VERSION 5.8 ;
BUSBITCHARS "[]" ;
DIVIDERCHAR "/" ;

PROPERTYDEFINITIONS
  MACRO pathCL STRING ;
  MACRO arrayDisplay STRING ;
  MACRO instLabel STRING ;
  MACRO startLevel INTEGER ;
  MACRO stopLevel INTEGER ;
  MACRO scrollPercent INTEGER ;
  MACRO gridSpacing REAL ;
  MACRO gridMultiple INTEGER ;
  MACRO xSnapSpacing REAL ;
  MACRO ySnapSpacing REAL ;
  MACRO snapMode STRING ;
  MACRO segSnapMode STRING ;
  MACRO instanceDrawingMode STRING ;
  MACRO lppVisibilityMode STRING ;
  MACRO filterSize REAL ;
  MACRO filterSizeDrawingStyle STRING ;
  MACRO displayResolution STRING ;
  MACRO dimmingScope STRING ;
  MACRO dimmingIntensity INTEGER ;
  MACRO autoZoomMode STRING ;
  MACRO autoZoomScale INTEGER ;
  MACRO mergeScope STRING ;
  LAYER LEF58_TYPE STRING ;
END PROPERTYDEFINITIONS


LAYER well
  TYPE MASTERSLICE ;
  PROPERTY LEF58_TYPE "TYPE NWELL ;" ;
END well

LAYER Gate
  TYPE MASTERSLICE ;
END Gate

LAYER Active
  TYPE MASTERSLICE ;
  PROPERTY LEF58_TYPE "TYPE DIFFUSION ;" ;
END Active

LAYER LISD
  TYPE MASTERSLICE ;
  PROPERTY LEF58_TYPE "TYPE MEOL ;" ;
END LISD

LAYER LIG
  TYPE MASTERSLICE ;
  PROPERTY LEF58_TYPE "TYPE MEOL ;" ;
END LIG


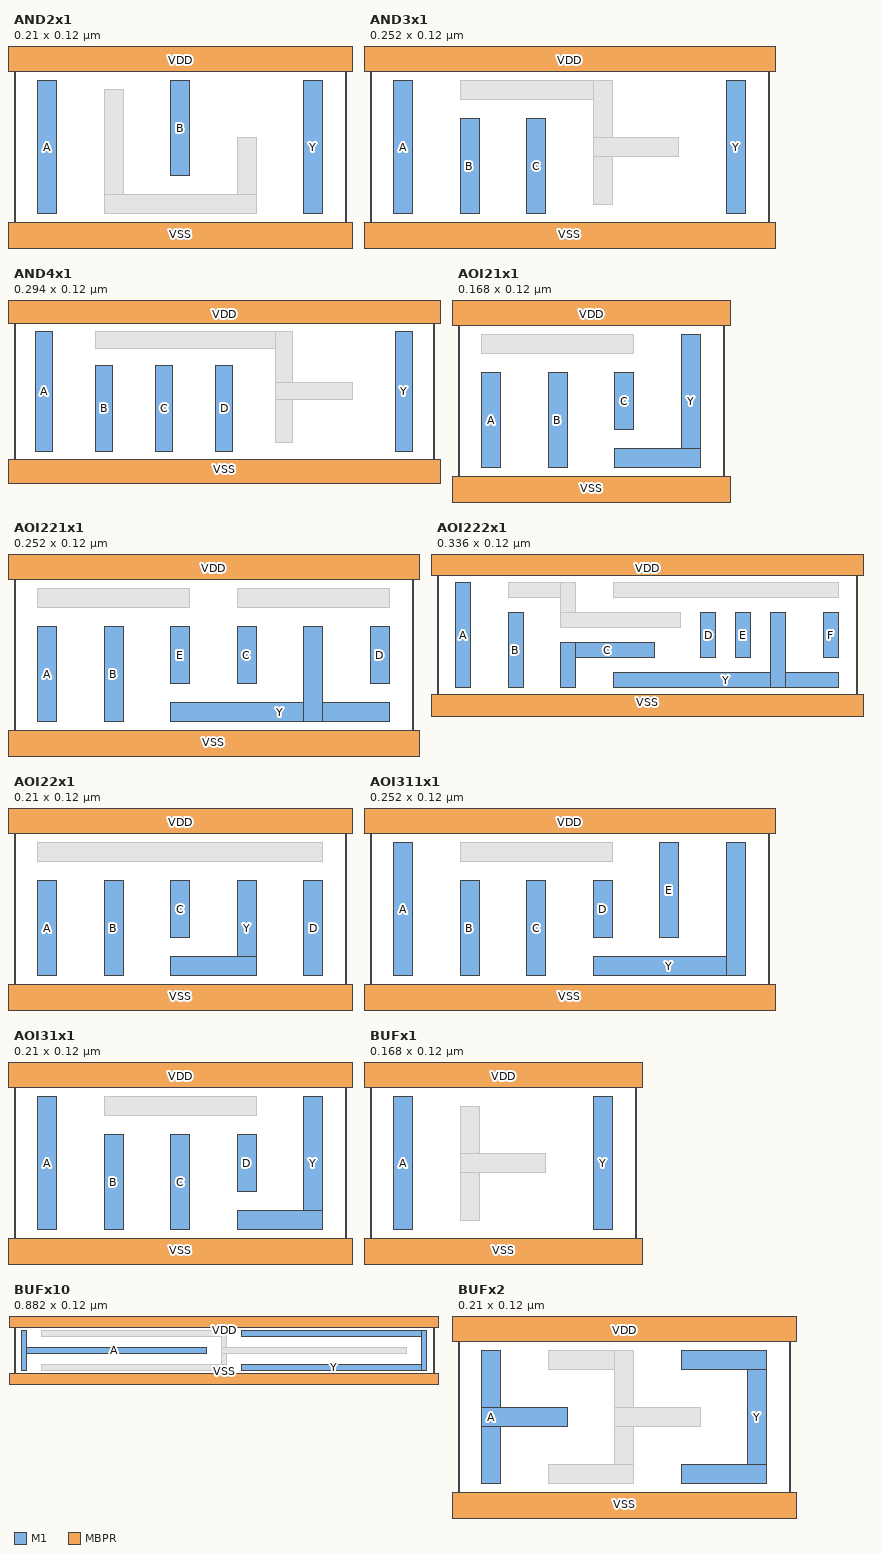
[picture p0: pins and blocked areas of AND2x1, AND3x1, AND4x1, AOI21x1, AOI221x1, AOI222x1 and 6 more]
MACRO AND2x1
  CLASS CORE ;
  ORIGIN 0 0 ;
  FOREIGN AND2x1 0 0 ;
  SIZE 0.21 BY 0.12 ;
  SYMMETRY X Y ;
  SITE coreSite ;
  PIN A
    DIRECTION INPUT ;
    USE SIGNAL ;
    PORT
      LAYER M1 ;
        RECT 0.015 0.018 0.027 0.102 ;
    END
  END A
  PIN B
    DIRECTION INPUT ;
    USE SIGNAL ;
    PORT
      LAYER M1 ;
        RECT 0.099 0.042 0.111 0.102 ;
    END
  END B
  PIN VDD
    DIRECTION INOUT ;
    USE POWER ;
    SHAPE ABUTMENT ;
    PORT
      LAYER MBPR ;
        RECT -0.009 0.1075 0.219 0.1325 ;
    END
  END VDD
  PIN VSS
    DIRECTION INOUT ;
    USE GROUND ;
    SHAPE ABUTMENT ;
    PORT
      LAYER MBPR ;
        RECT -0.009 -0.0125 0.219 0.0125 ;
    END
  END VSS
  PIN Y
    DIRECTION OUTPUT ;
    USE SIGNAL ;
    PORT
      LAYER M1 ;
        RECT 0.183 0.018 0.195 0.102 ;
    END
  END Y
  OBS
    LAYER M1 ;
      RECT 0.057 0.018 0.069 0.096 ;
      RECT 0.141 0.018 0.153 0.066 ;
      RECT 0.057 0.018 0.153 0.03 ;
    LAYER VBPR ;
      RECT 0.011 -0.006 0.031 0.006 ;
      RECT 0.137 -0.006 0.157 0.006 ;
      RECT 0.011 0.114 0.031 0.126 ;
      RECT 0.137 0.114 0.157 0.126 ;
      RECT 0.095 0.114 0.115 0.126 ;
  END
END AND2x1

MACRO AND3x1
  CLASS CORE ;
  ORIGIN 0 0 ;
  FOREIGN AND3x1 0 0 ;
  SIZE 0.252 BY 0.12 ;
  SYMMETRY X Y ;
  SITE coreSite ;
  PIN A
    DIRECTION INPUT ;
    USE SIGNAL ;
    PORT
      LAYER M1 ;
        RECT 0.015 0.018 0.027 0.102 ;
    END
  END A
  PIN B
    DIRECTION INPUT ;
    USE SIGNAL ;
    PORT
      LAYER M1 ;
        RECT 0.057 0.018 0.069 0.078 ;
    END
  END B
  PIN C
    DIRECTION INPUT ;
    USE SIGNAL ;
    PORT
      LAYER M1 ;
        RECT 0.099 0.018 0.111 0.078 ;
    END
  END C
  PIN VDD
    DIRECTION INOUT ;
    USE POWER ;
    SHAPE ABUTMENT ;
    PORT
      LAYER MBPR ;
        RECT -0.009 0.1075 0.261 0.1325 ;
    END
  END VDD
  PIN VSS
    DIRECTION INOUT ;
    USE GROUND ;
    SHAPE ABUTMENT ;
    PORT
      LAYER MBPR ;
        RECT -0.009 -0.0125 0.261 0.0125 ;
    END
  END VSS
  PIN Y
    DIRECTION OUTPUT ;
    USE SIGNAL ;
    PORT
      LAYER M1 ;
        RECT 0.225 0.018 0.237 0.102 ;
    END
  END Y
  OBS
    LAYER M1 ;
      RECT 0.057 0.09 0.153 0.102 ;
      RECT 0.141 0.024 0.153 0.102 ;
      RECT 0.141 0.054 0.195 0.066 ;
    LAYER VBPR ;
      RECT 0.011 -0.006 0.031 0.006 ;
      RECT 0.179 -0.006 0.199 0.006 ;
      RECT 0.011 0.114 0.031 0.126 ;
      RECT 0.179 0.114 0.199 0.126 ;
      RECT 0.095 0.114 0.115 0.126 ;
  END
END AND3x1

MACRO AND4x1
  CLASS CORE ;
  ORIGIN 0 0 ;
  FOREIGN AND4x1 0 0 ;
  SIZE 0.294 BY 0.12 ;
  SYMMETRY X Y ;
  SITE coreSite ;
  PIN A
    DIRECTION INPUT ;
    USE SIGNAL ;
    PORT
      LAYER M1 ;
        RECT 0.015 0.018 0.027 0.102 ;
    END
  END A
  PIN B
    DIRECTION INPUT ;
    USE SIGNAL ;
    PORT
      LAYER M1 ;
        RECT 0.057 0.018 0.069 0.078 ;
    END
  END B
  PIN C
    DIRECTION INPUT ;
    USE SIGNAL ;
    PORT
      LAYER M1 ;
        RECT 0.099 0.018 0.111 0.078 ;
    END
  END C
  PIN D
    DIRECTION INPUT ;
    USE SIGNAL ;
    PORT
      LAYER M1 ;
        RECT 0.141 0.018 0.153 0.078 ;
    END
  END D
  PIN VDD
    DIRECTION INOUT ;
    USE POWER ;
    SHAPE ABUTMENT ;
    PORT
      LAYER MBPR ;
        RECT -0.009 0.1075 0.303 0.1325 ;
    END
  END VDD
  PIN VSS
    DIRECTION INOUT ;
    USE GROUND ;
    SHAPE ABUTMENT ;
    PORT
      LAYER MBPR ;
        RECT -0.009 -0.0125 0.303 0.0125 ;
    END
  END VSS
  PIN Y
    DIRECTION OUTPUT ;
    USE SIGNAL ;
    PORT
      LAYER M1 ;
        RECT 0.267 0.018 0.279 0.102 ;
    END
  END Y
  OBS
    LAYER M1 ;
      RECT 0.057 0.09 0.195 0.102 ;
      RECT 0.183 0.024 0.195 0.102 ;
      RECT 0.183 0.054 0.237 0.066 ;
    LAYER VBPR ;
      RECT 0.011 -0.006 0.031 0.006 ;
      RECT 0.221 -0.006 0.241 0.006 ;
      RECT 0.011 0.114 0.031 0.126 ;
      RECT 0.221 0.114 0.241 0.126 ;
      RECT 0.095 0.114 0.115 0.126 ;
      RECT 0.179 0.114 0.199 0.126 ;
  END
END AND4x1

MACRO AOI21x1
  CLASS CORE ;
  ORIGIN 0 0 ;
  FOREIGN AOI21x1 0 0 ;
  SIZE 0.168 BY 0.12 ;
  SYMMETRY X Y ;
  SITE coreSite ;
  PIN A
    DIRECTION INPUT ;
    USE SIGNAL ;
    PORT
      LAYER M1 ;
        RECT 0.015 0.018 0.027 0.078 ;
    END
  END A
  PIN B
    DIRECTION INPUT ;
    USE SIGNAL ;
    PORT
      LAYER M1 ;
        RECT 0.057 0.018 0.069 0.078 ;
    END
  END B
  PIN C
    DIRECTION INPUT ;
    USE SIGNAL ;
    PORT
      LAYER M1 ;
        RECT 0.099 0.042 0.111 0.078 ;
    END
  END C
  PIN VDD
    DIRECTION INOUT ;
    USE POWER ;
    SHAPE ABUTMENT ;
    PORT
      LAYER MBPR ;
        RECT -0.009 0.1075 0.177 0.1325 ;
    END
  END VDD
  PIN VSS
    DIRECTION INOUT ;
    USE GROUND ;
    SHAPE ABUTMENT ;
    PORT
      LAYER MBPR ;
        RECT -0.009 -0.0125 0.177 0.0125 ;
    END
  END VSS
  PIN Y
    DIRECTION OUTPUT ;
    USE SIGNAL ;
    PORT
      LAYER M1 ;
        RECT 0.141 0.018 0.153 0.102 ;
        RECT 0.099 0.018 0.153 0.03 ;
    END
  END Y
  OBS
    LAYER M1 ;
      RECT 0.015 0.09 0.111 0.102 ;
    LAYER VBPR ;
      RECT 0.011 -0.006 0.031 0.006 ;
      RECT 0.137 -0.006 0.157 0.006 ;
      RECT 0.053 0.114 0.073 0.126 ;
  END
END AOI21x1

MACRO AOI221x1
  CLASS CORE ;
  ORIGIN 0 0 ;
  FOREIGN AOI221x1 0 0 ;
  SIZE 0.252 BY 0.12 ;
  SYMMETRY X Y ;
  SITE coreSite ;
  PIN A
    DIRECTION INPUT ;
    USE SIGNAL ;
    PORT
      LAYER M1 ;
        RECT 0.015 0.018 0.027 0.078 ;
    END
  END A
  PIN B
    DIRECTION INPUT ;
    USE SIGNAL ;
    PORT
      LAYER M1 ;
        RECT 0.057 0.018 0.069 0.078 ;
    END
  END B
  PIN C
    DIRECTION INPUT ;
    USE SIGNAL ;
    PORT
      LAYER M1 ;
        RECT 0.141 0.042 0.153 0.078 ;
    END
  END C
  PIN D
    DIRECTION INPUT ;
    USE SIGNAL ;
    PORT
      LAYER M1 ;
        RECT 0.225 0.042 0.237 0.078 ;
    END
  END D
  PIN E
    DIRECTION INPUT ;
    USE SIGNAL ;
    PORT
      LAYER M1 ;
        RECT 0.099 0.042 0.111 0.078 ;
    END
  END E
  PIN VDD
    DIRECTION INOUT ;
    USE POWER ;
    SHAPE ABUTMENT ;
    PORT
      LAYER MBPR ;
        RECT -0.009 0.1075 0.261 0.1325 ;
    END
  END VDD
  PIN VSS
    DIRECTION INOUT ;
    USE GROUND ;
    SHAPE ABUTMENT ;
    PORT
      LAYER MBPR ;
        RECT -0.009 -0.0125 0.261 0.0125 ;
    END
  END VSS
  PIN Y
    DIRECTION OUTPUT ;
    USE SIGNAL ;
    PORT
      LAYER M1 ;
        RECT 0.099 0.018 0.237 0.03 ;
        RECT 0.183 0.018 0.195 0.078 ;
    END
  END Y
  OBS
    LAYER M1 ;
      RECT 0.141 0.09 0.237 0.102 ;
      RECT 0.015 0.09 0.111 0.102 ;
    LAYER VBPR ;
      RECT 0.011 -0.006 0.031 0.006 ;
      RECT 0.137 -0.006 0.157 0.006 ;
      RECT 0.053 0.114 0.073 0.126 ;
  END
END AOI221x1

MACRO AOI222x1
  CLASS CORE ;
  ORIGIN 0 0 ;
  FOREIGN AOI222x1 0 0 ;
  SIZE 0.336 BY 0.12 ;
  SYMMETRY X Y ;
  SITE coreSite ;
  PIN A
    DIRECTION INPUT ;
    USE SIGNAL ;
    PORT
      LAYER M1 ;
        RECT 0.015 0.018 0.027 0.102 ;
    END
  END A
  PIN B
    DIRECTION INPUT ;
    USE SIGNAL ;
    PORT
      LAYER M1 ;
        RECT 0.057 0.018 0.069 0.078 ;
    END
  END B
  PIN C
    DIRECTION INPUT ;
    USE SIGNAL ;
    PORT
      LAYER M1 ;
        RECT 0.099 0.042 0.174 0.054 ;
        RECT 0.099 0.018 0.111 0.054 ;
    END
  END C
  PIN D
    DIRECTION INPUT ;
    USE SIGNAL ;
    PORT
      LAYER M1 ;
        RECT 0.211 0.042 0.223 0.078 ;
    END
  END D
  PIN E
    DIRECTION INPUT ;
    USE SIGNAL ;
    PORT
      LAYER M1 ;
        RECT 0.239 0.042 0.251 0.078 ;
    END
  END E
  PIN F
    DIRECTION INPUT ;
    USE SIGNAL ;
    PORT
      LAYER M1 ;
        RECT 0.309 0.042 0.321 0.078 ;
    END
  END F
  PIN VDD
    DIRECTION INOUT ;
    USE POWER ;
    SHAPE ABUTMENT ;
    PORT
      LAYER MBPR ;
        RECT -0.009 0.1075 0.345 0.1325 ;
    END
  END VDD
  PIN VSS
    DIRECTION INOUT ;
    USE GROUND ;
    SHAPE ABUTMENT ;
    PORT
      LAYER MBPR ;
        RECT -0.009 -0.0125 0.345 0.0125 ;
    END
  END VSS
  PIN Y
    DIRECTION OUTPUT ;
    USE SIGNAL ;
    PORT
      LAYER M1 ;
        RECT 0.141 0.018 0.321 0.03 ;
        RECT 0.267 0.018 0.279 0.078 ;
    END
  END Y
  OBS
    LAYER M1 ;
      RECT 0.057 0.09 0.111 0.102 ;
      RECT 0.099 0.066 0.111 0.102 ;
      RECT 0.099 0.066 0.195 0.078 ;
      RECT 0.141 0.09 0.321 0.102 ;
    LAYER VBPR ;
      RECT 0.011 -0.006 0.031 0.006 ;
      RECT 0.221 -0.006 0.241 0.006 ;
      RECT 0.011 0.114 0.031 0.126 ;
      RECT 0.095 0.114 0.115 0.126 ;
  END
END AOI222x1

MACRO AOI22x1
  CLASS CORE ;
  ORIGIN 0 0 ;
  FOREIGN AOI22x1 0 0 ;
  SIZE 0.21 BY 0.12 ;
  SYMMETRY X Y ;
  SITE coreSite ;
  PIN A
    DIRECTION INPUT ;
    USE SIGNAL ;
    PORT
      LAYER M1 ;
        RECT 0.015 0.018 0.027 0.078 ;
    END
  END A
  PIN B
    DIRECTION INPUT ;
    USE SIGNAL ;
    PORT
      LAYER M1 ;
        RECT 0.057 0.018 0.069 0.078 ;
    END
  END B
  PIN C
    DIRECTION INPUT ;
    USE SIGNAL ;
    PORT
      LAYER M1 ;
        RECT 0.099 0.042 0.111 0.078 ;
    END
  END C
  PIN D
    DIRECTION INPUT ;
    USE SIGNAL ;
    PORT
      LAYER M1 ;
        RECT 0.183 0.018 0.195 0.078 ;
    END
  END D
  PIN VDD
    DIRECTION INOUT ;
    USE POWER ;
    SHAPE ABUTMENT ;
    PORT
      LAYER MBPR ;
        RECT -0.009 0.1075 0.219 0.1325 ;
    END
  END VDD
  PIN VSS
    DIRECTION INOUT ;
    USE GROUND ;
    SHAPE ABUTMENT ;
    PORT
      LAYER MBPR ;
        RECT -0.009 -0.0125 0.219 0.0125 ;
    END
  END VSS
  PIN Y
    DIRECTION OUTPUT ;
    USE SIGNAL ;
    PORT
      LAYER M1 ;
        RECT 0.141 0.018 0.153 0.078 ;
        RECT 0.099 0.018 0.153 0.03 ;
    END
  END Y
  OBS
    LAYER M1 ;
      RECT 0.015 0.09 0.195 0.102 ;
    LAYER VBPR ;
      RECT 0.011 -0.006 0.031 0.006 ;
      RECT 0.179 -0.006 0.199 0.006 ;
      RECT 0.053 0.114 0.073 0.126 ;
  END
END AOI22x1

MACRO AOI311x1
  CLASS CORE ;
  ORIGIN 0 0 ;
  FOREIGN AOI311x1 0 0 ;
  SIZE 0.252 BY 0.12 ;
  SYMMETRY X Y ;
  SITE coreSite ;
  PIN A
    DIRECTION INPUT ;
    USE SIGNAL ;
    PORT
      LAYER M1 ;
        RECT 0.015 0.018 0.027 0.102 ;
    END
  END A
  PIN B
    DIRECTION INPUT ;
    USE SIGNAL ;
    PORT
      LAYER M1 ;
        RECT 0.057 0.018 0.069 0.078 ;
    END
  END B
  PIN C
    DIRECTION INPUT ;
    USE SIGNAL ;
    PORT
      LAYER M1 ;
        RECT 0.099 0.018 0.111 0.078 ;
    END
  END C
  PIN D
    DIRECTION INPUT ;
    USE SIGNAL ;
    PORT
      LAYER M1 ;
        RECT 0.141 0.042 0.153 0.078 ;
    END
  END D
  PIN E
    DIRECTION INPUT ;
    USE SIGNAL ;
    PORT
      LAYER M1 ;
        RECT 0.183 0.042 0.195 0.102 ;
    END
  END E
  PIN VDD
    DIRECTION INOUT ;
    USE POWER ;
    SHAPE ABUTMENT ;
    PORT
      LAYER MBPR ;
        RECT -0.009 0.1075 0.261 0.1325 ;
    END
  END VDD
  PIN VSS
    DIRECTION INOUT ;
    USE GROUND ;
    SHAPE ABUTMENT ;
    PORT
      LAYER MBPR ;
        RECT -0.009 -0.0125 0.261 0.0125 ;
    END
  END VSS
  PIN Y
    DIRECTION OUTPUT ;
    USE SIGNAL ;
    PORT
      LAYER M1 ;
        RECT 0.225 0.018 0.237 0.102 ;
        RECT 0.141 0.018 0.237 0.03 ;
    END
  END Y
  OBS
    LAYER M1 ;
      RECT 0.057 0.09 0.153 0.102 ;
    LAYER VBPR ;
      RECT 0.011 -0.006 0.031 0.006 ;
      RECT 0.179 -0.006 0.199 0.006 ;
      RECT 0.011 0.114 0.031 0.126 ;
      RECT 0.095 0.114 0.115 0.126 ;
  END
END AOI311x1

MACRO AOI31x1
  CLASS CORE ;
  ORIGIN 0 0 ;
  FOREIGN AOI31x1 0 0 ;
  SIZE 0.21 BY 0.12 ;
  SYMMETRY X Y ;
  SITE coreSite ;
  PIN A
    DIRECTION INPUT ;
    USE SIGNAL ;
    PORT
      LAYER M1 ;
        RECT 0.015 0.018 0.027 0.102 ;
    END
  END A
  PIN B
    DIRECTION INPUT ;
    USE SIGNAL ;
    PORT
      LAYER M1 ;
        RECT 0.057 0.018 0.069 0.078 ;
    END
  END B
  PIN C
    DIRECTION INPUT ;
    USE SIGNAL ;
    PORT
      LAYER M1 ;
        RECT 0.099 0.018 0.111 0.078 ;
    END
  END C
  PIN D
    DIRECTION INPUT ;
    USE SIGNAL ;
    PORT
      LAYER M1 ;
        RECT 0.141 0.042 0.153 0.078 ;
    END
  END D
  PIN VDD
    DIRECTION INOUT ;
    USE POWER ;
    SHAPE ABUTMENT ;
    PORT
      LAYER MBPR ;
        RECT -0.009 0.1075 0.219 0.1325 ;
    END
  END VDD
  PIN VSS
    DIRECTION INOUT ;
    USE GROUND ;
    SHAPE ABUTMENT ;
    PORT
      LAYER MBPR ;
        RECT -0.009 -0.0125 0.219 0.0125 ;
    END
  END VSS
  PIN Y
    DIRECTION OUTPUT ;
    USE SIGNAL ;
    PORT
      LAYER M1 ;
        RECT 0.183 0.018 0.195 0.102 ;
        RECT 0.141 0.018 0.195 0.03 ;
    END
  END Y
  OBS
    LAYER M1 ;
      RECT 0.057 0.09 0.153 0.102 ;
    LAYER VBPR ;
      RECT 0.011 -0.006 0.031 0.006 ;
      RECT 0.179 -0.006 0.199 0.006 ;
      RECT 0.011 0.114 0.031 0.126 ;
      RECT 0.095 0.114 0.115 0.126 ;
  END
END AOI31x1

MACRO BUFx1
  CLASS CORE ;
  ORIGIN 0 0 ;
  FOREIGN BUFx1 0 0 ;
  SIZE 0.168 BY 0.12 ;
  SYMMETRY X Y ;
  SITE coreSite ;
  PIN A
    DIRECTION INPUT ;
    USE SIGNAL ;
    PORT
      LAYER M1 ;
        RECT 0.015 0.018 0.027 0.102 ;
    END
  END A
  PIN VDD
    DIRECTION INOUT ;
    USE POWER ;
    SHAPE ABUTMENT ;
    PORT
      LAYER MBPR ;
        RECT -0.009 0.1075 0.177 0.1325 ;
    END
  END VDD
  PIN VSS
    DIRECTION INOUT ;
    USE GROUND ;
    SHAPE ABUTMENT ;
    PORT
      LAYER MBPR ;
        RECT -0.009 -0.0125 0.177 0.0125 ;
    END
  END VSS
  PIN Y
    DIRECTION OUTPUT ;
    USE SIGNAL ;
    PORT
      LAYER M1 ;
        RECT 0.141 0.018 0.153 0.102 ;
    END
  END Y
  OBS
    LAYER M1 ;
      RECT 0.057 0.024 0.069 0.096 ;
      RECT 0.057 0.054 0.111 0.066 ;
    LAYER VBPR ;
      RECT 0.011 -0.006 0.031 0.006 ;
      RECT 0.095 -0.006 0.115 0.006 ;
      RECT 0.011 0.114 0.031 0.126 ;
      RECT 0.095 0.114 0.115 0.126 ;
  END
END BUFx1

MACRO BUFx10
  CLASS CORE ;
  ORIGIN 0 0 ;
  FOREIGN BUFx10 0 0 ;
  SIZE 0.882 BY 0.12 ;
  SYMMETRY X Y ;
  SITE coreSite ;
  PIN A
    DIRECTION INPUT ;
    USE SIGNAL ;
    PORT
      LAYER M1 ;
        RECT 0.015 0.054 0.405 0.066 ;
        RECT 0.015 0.018 0.027 0.102 ;
    END
  END A
  PIN VDD
    DIRECTION INOUT ;
    USE POWER ;
    SHAPE ABUTMENT ;
    PORT
      LAYER MBPR ;
        RECT -0.009 0.1075 0.891 0.1325 ;
    END
  END VDD
  PIN VSS
    DIRECTION INOUT ;
    USE GROUND ;
    SHAPE ABUTMENT ;
    PORT
      LAYER MBPR ;
        RECT -0.009 -0.0125 0.891 0.0125 ;
    END
  END VSS
  PIN Y
    DIRECTION OUTPUT ;
    USE SIGNAL ;
    PORT
      LAYER M1 ;
        RECT 0.477 0.09 0.867 0.102 ;
        RECT 0.855 0.018 0.867 0.102 ;
        RECT 0.477 0.018 0.867 0.03 ;
    END
  END Y
  OBS
    LAYER M1 ;
      RECT 0.057 0.09 0.447 0.102 ;
      RECT 0.435 0.018 0.447 0.102 ;
      RECT 0.435 0.054 0.825 0.066 ;
      RECT 0.057 0.018 0.447 0.03 ;
    LAYER VBPR ;
      RECT 0.011 -0.006 0.031 0.006 ;
      RECT 0.011 0.114 0.031 0.126 ;
      RECT 0.095 -0.006 0.115 0.006 ;
      RECT 0.095 0.114 0.115 0.126 ;
      RECT 0.179 -0.006 0.199  0.006 ;
      RECT 0.179  0.114 0.199  0.126 ;
      RECT 0.263 -0.006 0.283  0.006 ;
      RECT 0.263  0.114 0.283  0.126 ;
      RECT 0.347 -0.006 0.367  0.006 ;
      RECT 0.347  0.114 0.367  0.126 ;
      RECT 0.431 -0.006 0.451  0.006 ;
      RECT 0.431  0.114 0.451  0.126 ;
      RECT 0.515 -0.006 0.535  0.006 ;
      RECT 0.515  0.114 0.535  0.126 ;
      RECT 0.599 -0.006 0.619  0.006 ;
      RECT 0.599  0.114 0.619  0.126 ;
      RECT 0.683 -0.006 0.703  0.006 ;
      RECT 0.683  0.114 0.703  0.126 ;
      RECT 0.767 -0.006 0.787  0.006 ;
      RECT 0.767  0.114 0.787  0.126 ;
      RECT 0.851 -0.006 0.871  0.006 ;
      RECT 0.851  0.114 0.871  0.126 ;
  END
  PROPERTY pathCL "yes" ;
  PROPERTY arrayDisplay "Full" ;
  PROPERTY instLabel "master" ;
  PROPERTY startLevel 0 ;
  PROPERTY stopLevel 0 ;
  PROPERTY scrollPercent 25 ;
  PROPERTY gridSpacing 1 ;
  PROPERTY gridMultiple 5 ;
  PROPERTY xSnapSpacing 0.001 ;
  PROPERTY ySnapSpacing 0.001 ;
  PROPERTY snapMode "orthogonal" ;
  PROPERTY segSnapMode "orthogonal" ;
  PROPERTY instanceDrawingMode "BBox" ;
  PROPERTY lppVisibilityMode "donotCheckValidity" ;
  PROPERTY filterSize 6 ;
  PROPERTY filterSizeDrawingStyle "empty" ;
  PROPERTY displayResolution "Medium" ;
  PROPERTY dimmingScope "none" ;
  PROPERTY dimmingIntensity 50 ;
  PROPERTY autoZoomMode "Pan" ;
  PROPERTY autoZoomScale 90 ;
  PROPERTY mergeScope "pcells" ;
END BUFx10

MACRO BUFx2
  CLASS CORE ;
  ORIGIN 0 0 ;
  FOREIGN BUFx2 0 0 ;
  SIZE 0.21 BY 0.12 ;
  SYMMETRY X Y ;
  SITE coreSite ;
  PIN A
    DIRECTION INPUT ;
    USE SIGNAL ;
    PORT
      LAYER M1 ;
        RECT 0.015 0.054 0.069 0.066 ;
        RECT 0.015 0.018 0.027 0.102 ;
    END
  END A
  PIN VDD
    DIRECTION INOUT ;
    USE POWER ;
    SHAPE ABUTMENT ;
    PORT
      LAYER MBPR ;
        RECT -0.009 0.1075 0.219 0.1325 ;
    END
  END VDD
  PIN VSS
    DIRECTION INOUT ;
    USE GROUND ;
    SHAPE ABUTMENT ;
    PORT
      LAYER MBPR ;
        RECT -0.009 -0.0125 0.219 0.0125 ;
    END
  END VSS
  PIN Y
    DIRECTION OUTPUT ;
    USE SIGNAL ;
    PORT
      LAYER M1 ;
        RECT 0.141 0.09 0.195 0.102 ;
        RECT 0.183 0.018 0.195 0.102 ;
        RECT 0.141 0.018 0.195 0.03 ;
    END
  END Y
  OBS
    LAYER M1 ;
      RECT 0.057 0.09 0.111 0.102 ;
      RECT 0.099 0.018 0.111 0.102 ;
      RECT 0.099 0.054 0.153 0.066 ;
      RECT 0.057 0.018 0.111 0.03 ;
    LAYER VBPR ;
      RECT 0.011 -0.006 0.031 0.006 ;
      RECT 0.011 0.114 0.031 0.126 ;
      RECT 0.095 -0.006 0.115 0.006 ;
      RECT 0.095 0.114 0.115 0.126 ;
      RECT 0.179 -0.006 0.199  0.006 ;
      RECT 0.179  0.114 0.199  0.126 ;
  END
END BUFx2

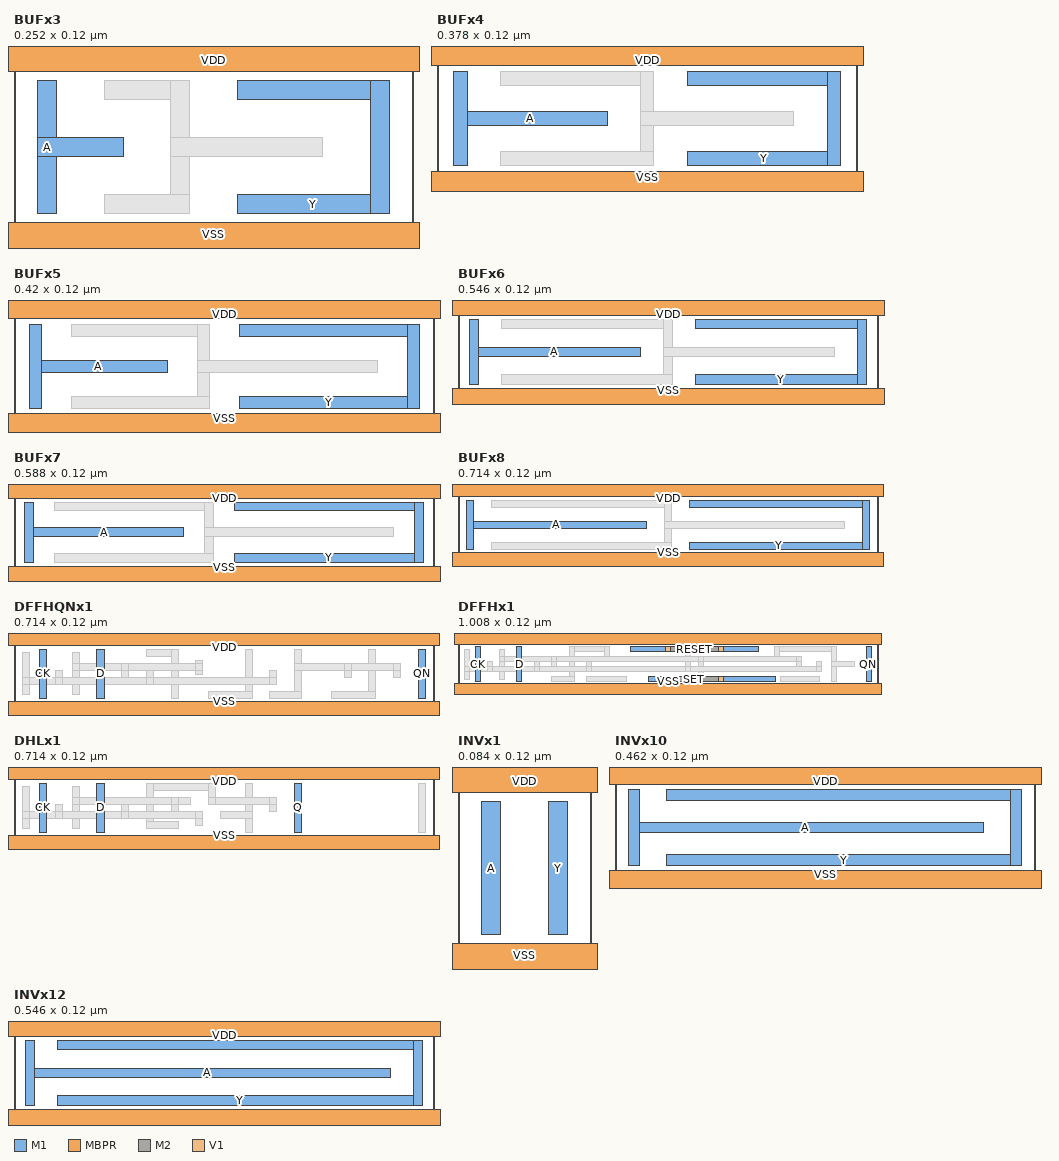
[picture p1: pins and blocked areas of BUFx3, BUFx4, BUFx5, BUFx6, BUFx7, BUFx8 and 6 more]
MACRO BUFx3
  CLASS CORE ;
  ORIGIN 0 0 ;
  FOREIGN BUFx3 0 0 ;
  SIZE 0.252 BY 0.12 ;
  SYMMETRY X Y ;
  SITE coreSite ;
  PIN A
    DIRECTION INPUT ;
    USE SIGNAL ;
    PORT
      LAYER M1 ;
        RECT 0.015 0.054 0.069 0.066 ;
        RECT 0.015 0.018 0.027 0.102 ;
    END
  END A
  PIN VDD
    DIRECTION INOUT ;
    USE POWER ;
    SHAPE ABUTMENT ;
    PORT
      LAYER MBPR ;
        RECT -0.009 0.1075 0.261 0.1325 ;
    END
  END VDD
  PIN VSS
    DIRECTION INOUT ;
    USE GROUND ;
    SHAPE ABUTMENT ;
    PORT
      LAYER MBPR ;
        RECT -0.009 -0.0125 0.261 0.0125 ;
    END
  END VSS
  PIN Y
    DIRECTION OUTPUT ;
    USE SIGNAL ;
    PORT
      LAYER M1 ;
        RECT 0.141 0.09 0.237 0.102 ;
        RECT 0.225 0.018 0.237 0.102 ;
        RECT 0.141 0.018 0.237 0.03 ;
    END
  END Y
  OBS
    LAYER M1 ;
      RECT 0.057 0.09 0.111 0.102 ;
      RECT 0.099 0.018 0.111 0.102 ;
      RECT 0.099 0.054 0.195 0.066 ;
      RECT 0.057 0.018 0.111 0.03 ;
    LAYER VBPR ;
      RECT 0.011 -0.006 0.031 0.006 ;
      RECT 0.011 0.114 0.031 0.126 ;
      RECT 0.095 -0.006 0.115 0.006 ;
      RECT 0.095 0.114 0.115 0.126 ;
      RECT 0.179 -0.006 0.199  0.006 ;
      RECT 0.179  0.114 0.199  0.126 ;
  END
  PROPERTY pathCL "yes" ;
  PROPERTY arrayDisplay "Full" ;
  PROPERTY instLabel "master" ;
  PROPERTY startLevel 0 ;
  PROPERTY stopLevel 0 ;
  PROPERTY scrollPercent 25 ;
  PROPERTY gridSpacing 1 ;
  PROPERTY gridMultiple 5 ;
  PROPERTY xSnapSpacing 0.001 ;
  PROPERTY ySnapSpacing 0.001 ;
  PROPERTY snapMode "orthogonal" ;
  PROPERTY segSnapMode "orthogonal" ;
  PROPERTY instanceDrawingMode "BBox" ;
  PROPERTY lppVisibilityMode "donotCheckValidity" ;
  PROPERTY filterSize 6 ;
  PROPERTY filterSizeDrawingStyle "empty" ;
  PROPERTY displayResolution "Medium" ;
  PROPERTY dimmingScope "none" ;
  PROPERTY dimmingIntensity 50 ;
  PROPERTY autoZoomMode "Pan" ;
  PROPERTY autoZoomScale 90 ;
  PROPERTY mergeScope "pcells" ;
END BUFx3

MACRO BUFx4
  CLASS CORE ;
  ORIGIN 0 0 ;
  FOREIGN BUFx4 0 0 ;
  SIZE 0.378 BY 0.12 ;
  SYMMETRY X Y ;
  SITE coreSite ;
  PIN A
    DIRECTION INPUT ;
    USE SIGNAL ;
    PORT
      LAYER M1 ;
        RECT 0.015 0.054 0.153 0.066 ;
        RECT 0.015 0.018 0.027 0.102 ;
    END
  END A
  PIN VDD
    DIRECTION INOUT ;
    USE POWER ;
    SHAPE ABUTMENT ;
    PORT
      LAYER MBPR ;
        RECT -0.009 0.1075 0.387 0.1325 ;
    END
  END VDD
  PIN VSS
    DIRECTION INOUT ;
    USE GROUND ;
    SHAPE ABUTMENT ;
    PORT
      LAYER MBPR ;
        RECT -0.009 -0.0125 0.387 0.0125 ;
    END
  END VSS
  PIN Y
    DIRECTION OUTPUT ;
    USE SIGNAL ;
    PORT
      LAYER M1 ;
        RECT 0.225 0.09 0.363 0.102 ;
        RECT 0.351 0.018 0.363 0.102 ;
        RECT 0.225 0.018 0.363 0.03 ;
    END
  END Y
  OBS
    LAYER M1 ;
      RECT 0.057 0.09 0.195 0.102 ;
      RECT 0.183 0.018 0.195 0.102 ;
      RECT 0.183 0.054 0.321 0.066 ;
      RECT 0.057 0.018 0.195 0.03 ;
    LAYER VBPR ;
      RECT 0.011 -0.006 0.031 0.006 ;
      RECT 0.011 0.114 0.031 0.126 ;
      RECT 0.095 -0.006 0.115 0.006 ;
      RECT 0.095 0.114 0.115 0.126 ;
      RECT 0.179 -0.006 0.199  0.006 ;
      RECT 0.179  0.114 0.199  0.126 ;
      RECT 0.263 -0.006 0.283  0.006 ;
      RECT 0.263  0.114 0.283  0.126 ;
      RECT 0.347 -0.006 0.367  0.006 ;
      RECT 0.347  0.114 0.367  0.126 ;
  END
  PROPERTY pathCL "yes" ;
  PROPERTY arrayDisplay "Full" ;
  PROPERTY instLabel "master" ;
  PROPERTY startLevel 0 ;
  PROPERTY stopLevel 0 ;
  PROPERTY scrollPercent 25 ;
  PROPERTY gridSpacing 1 ;
  PROPERTY gridMultiple 5 ;
  PROPERTY xSnapSpacing 0.001 ;
  PROPERTY ySnapSpacing 0.001 ;
  PROPERTY snapMode "orthogonal" ;
  PROPERTY segSnapMode "orthogonal" ;
  PROPERTY instanceDrawingMode "BBox" ;
  PROPERTY lppVisibilityMode "donotCheckValidity" ;
  PROPERTY filterSize 6 ;
  PROPERTY filterSizeDrawingStyle "empty" ;
  PROPERTY displayResolution "Medium" ;
  PROPERTY dimmingScope "none" ;
  PROPERTY dimmingIntensity 50 ;
  PROPERTY autoZoomMode "Pan" ;
  PROPERTY autoZoomScale 90 ;
  PROPERTY mergeScope "pcells" ;
END BUFx4

MACRO BUFx5
  CLASS CORE ;
  ORIGIN 0 0 ;
  FOREIGN BUFx5 0 0 ;
  SIZE 0.42 BY 0.12 ;
  SYMMETRY X Y ;
  SITE coreSite ;
  PIN A
    DIRECTION INPUT ;
    USE SIGNAL ;
    PORT
      LAYER M1 ;
        RECT 0.015 0.054 0.153 0.066 ;
        RECT 0.015 0.018 0.027 0.102 ;
    END
  END A
  PIN VDD
    DIRECTION INOUT ;
    USE POWER ;
    SHAPE ABUTMENT ;
    PORT
      LAYER MBPR ;
        RECT -0.009 0.1075 0.429 0.1325 ;
    END
  END VDD
  PIN VSS
    DIRECTION INOUT ;
    USE GROUND ;
    SHAPE ABUTMENT ;
    PORT
      LAYER MBPR ;
        RECT -0.009 -0.0125 0.429 0.0125 ;
    END
  END VSS
  PIN Y
    DIRECTION OUTPUT ;
    USE SIGNAL ;
    PORT
      LAYER M1 ;
        RECT 0.225 0.09 0.405 0.102 ;
        RECT 0.393 0.018 0.405 0.102 ;
        RECT 0.225 0.018 0.405 0.03 ;
    END
  END Y
  OBS
    LAYER M1 ;
      RECT 0.057 0.09 0.195 0.102 ;
      RECT 0.183 0.018 0.195 0.102 ;
      RECT 0.183 0.054 0.363 0.066 ;
      RECT 0.057 0.018 0.195 0.03 ;
    LAYER VBPR ;
      RECT 0.011 -0.006 0.031 0.006 ;
      RECT 0.011 0.114 0.031 0.126 ;
      RECT 0.095 -0.006 0.115 0.006 ;
      RECT 0.095 0.114 0.115 0.126 ;
      RECT 0.179 -0.006 0.199  0.006 ;
      RECT 0.179  0.114 0.199  0.126 ;
      RECT 0.263 -0.006 0.283  0.006 ;
      RECT 0.263  0.114 0.283  0.126 ;
      RECT 0.347 -0.006 0.367  0.006 ;
      RECT 0.347  0.114 0.367  0.126 ;
  END
  PROPERTY pathCL "yes" ;
  PROPERTY arrayDisplay "Full" ;
  PROPERTY instLabel "master" ;
  PROPERTY startLevel 0 ;
  PROPERTY stopLevel 0 ;
  PROPERTY scrollPercent 25 ;
  PROPERTY gridSpacing 1 ;
  PROPERTY gridMultiple 5 ;
  PROPERTY xSnapSpacing 0.001 ;
  PROPERTY ySnapSpacing 0.001 ;
  PROPERTY snapMode "orthogonal" ;
  PROPERTY segSnapMode "orthogonal" ;
  PROPERTY instanceDrawingMode "BBox" ;
  PROPERTY lppVisibilityMode "donotCheckValidity" ;
  PROPERTY filterSize 6 ;
  PROPERTY filterSizeDrawingStyle "empty" ;
  PROPERTY displayResolution "Medium" ;
  PROPERTY dimmingScope "none" ;
  PROPERTY dimmingIntensity 50 ;
  PROPERTY autoZoomMode "Pan" ;
  PROPERTY autoZoomScale 90 ;
  PROPERTY mergeScope "pcells" ;
END BUFx5

MACRO BUFx6
  CLASS CORE ;
  ORIGIN 0 0 ;
  FOREIGN BUFx6 0 0 ;
  SIZE 0.546 BY 0.12 ;
  SYMMETRY X Y ;
  SITE coreSite ;
  PIN A
    DIRECTION INPUT ;
    USE SIGNAL ;
    PORT
      LAYER M1 ;
        RECT 0.015 0.054 0.237 0.066 ;
        RECT 0.015 0.018 0.027 0.102 ;
    END
  END A
  PIN VDD
    DIRECTION INOUT ;
    USE POWER ;
    SHAPE ABUTMENT ;
    PORT
      LAYER MBPR ;
        RECT -0.009 0.1075 0.555 0.1325 ;
    END
  END VDD
  PIN VSS
    DIRECTION INOUT ;
    USE GROUND ;
    SHAPE ABUTMENT ;
    PORT
      LAYER MBPR ;
        RECT -0.009 -0.0125 0.555 0.0125 ;
    END
  END VSS
  PIN Y
    DIRECTION OUTPUT ;
    USE SIGNAL ;
    PORT
      LAYER M1 ;
        RECT 0.309 0.09 0.531 0.102 ;
        RECT 0.519 0.018 0.531 0.102 ;
        RECT 0.309 0.018 0.531 0.03 ;
    END
  END Y
  OBS
    LAYER M1 ;
      RECT 0.057 0.09 0.279 0.102 ;
      RECT 0.267 0.018 0.279 0.102 ;
      RECT 0.267 0.054 0.489 0.066 ;
      RECT 0.057 0.018 0.279 0.03 ;
    LAYER VBPR ;
      RECT 0.011 -0.006 0.031 0.006 ;
      RECT 0.011 0.114 0.031 0.126 ;
      RECT 0.095 -0.006 0.115 0.006 ;
      RECT 0.095 0.114 0.115 0.126 ;
      RECT 0.179 -0.006 0.199  0.006 ;
      RECT 0.179  0.114 0.199  0.126 ;
      RECT 0.263 -0.006 0.283  0.006 ;
      RECT 0.263  0.114 0.283  0.126 ;
      RECT 0.347 -0.006 0.367  0.006 ;
      RECT 0.347  0.114 0.367  0.126 ;
      RECT 0.431 -0.006 0.451  0.006 ;
      RECT 0.431  0.114 0.451  0.126 ;
      RECT 0.515 -0.006 0.535  0.006 ;
      RECT 0.515  0.114 0.535  0.126 ;
  END
  PROPERTY pathCL "yes" ;
  PROPERTY arrayDisplay "Full" ;
  PROPERTY instLabel "master" ;
  PROPERTY startLevel 0 ;
  PROPERTY stopLevel 0 ;
  PROPERTY scrollPercent 25 ;
  PROPERTY gridSpacing 1 ;
  PROPERTY gridMultiple 5 ;
  PROPERTY xSnapSpacing 0.001 ;
  PROPERTY ySnapSpacing 0.001 ;
  PROPERTY snapMode "orthogonal" ;
  PROPERTY segSnapMode "orthogonal" ;
  PROPERTY instanceDrawingMode "BBox" ;
  PROPERTY lppVisibilityMode "donotCheckValidity" ;
  PROPERTY filterSize 6 ;
  PROPERTY filterSizeDrawingStyle "empty" ;
  PROPERTY displayResolution "Medium" ;
  PROPERTY dimmingScope "none" ;
  PROPERTY dimmingIntensity 50 ;
  PROPERTY autoZoomMode "Pan" ;
  PROPERTY autoZoomScale 90 ;
  PROPERTY mergeScope "pcells" ;
END BUFx6

MACRO BUFx7
  CLASS CORE ;
  ORIGIN 0 0 ;
  FOREIGN BUFx7 0 0 ;
  SIZE 0.588 BY 0.12 ;
  SYMMETRY X Y ;
  SITE coreSite ;
  PIN A
    DIRECTION INPUT ;
    USE SIGNAL ;
    PORT
      LAYER M1 ;
        RECT 0.015 0.054 0.237 0.066 ;
        RECT 0.015 0.018 0.027 0.102 ;
    END
  END A
  PIN VDD
    DIRECTION INOUT ;
    USE POWER ;
    SHAPE ABUTMENT ;
    PORT
      LAYER MBPR ;
        RECT -0.009 0.1075 0.597 0.1325 ;
    END
  END VDD
  PIN VSS
    DIRECTION INOUT ;
    USE GROUND ;
    SHAPE ABUTMENT ;
    PORT
      LAYER MBPR ;
        RECT -0.009 -0.0125 0.597 0.0125 ;
    END
  END VSS
  PIN Y
    DIRECTION OUTPUT ;
    USE SIGNAL ;
    PORT
      LAYER M1 ;
        RECT 0.309 0.09 0.573 0.102 ;
        RECT 0.561 0.018 0.573 0.102 ;
        RECT 0.309 0.018 0.573 0.03 ;
    END
  END Y
  OBS
    LAYER M1 ;
      RECT 0.057 0.09 0.279 0.102 ;
      RECT 0.267 0.018 0.279 0.102 ;
      RECT 0.267 0.054 0.531 0.066 ;
      RECT 0.057 0.018 0.279 0.03 ;
    LAYER VBPR ;
      RECT 0.011 -0.006 0.031 0.006 ;
      RECT 0.011 0.114 0.031 0.126 ;
      RECT 0.095 -0.006 0.115 0.006 ;
      RECT 0.095 0.114 0.115 0.126 ;
      RECT 0.179 -0.006 0.199  0.006 ;
      RECT 0.179  0.114 0.199  0.126 ;
      RECT 0.263 -0.006 0.283  0.006 ;
      RECT 0.263  0.114 0.283  0.126 ;
      RECT 0.347 -0.006 0.367  0.006 ;
      RECT 0.347  0.114 0.367  0.126 ;
      RECT 0.431 -0.006 0.451  0.006 ;
      RECT 0.431  0.114 0.451  0.126 ;
      RECT 0.515 -0.006 0.535  0.006 ;
      RECT 0.515  0.114 0.535  0.126 ;
  END
  PROPERTY pathCL "yes" ;
  PROPERTY arrayDisplay "Full" ;
  PROPERTY instLabel "master" ;
  PROPERTY startLevel 0 ;
  PROPERTY stopLevel 0 ;
  PROPERTY scrollPercent 25 ;
  PROPERTY gridSpacing 1 ;
  PROPERTY gridMultiple 5 ;
  PROPERTY xSnapSpacing 0.001 ;
  PROPERTY ySnapSpacing 0.001 ;
  PROPERTY snapMode "orthogonal" ;
  PROPERTY segSnapMode "orthogonal" ;
  PROPERTY instanceDrawingMode "BBox" ;
  PROPERTY lppVisibilityMode "donotCheckValidity" ;
  PROPERTY filterSize 6 ;
  PROPERTY filterSizeDrawingStyle "empty" ;
  PROPERTY displayResolution "Medium" ;
  PROPERTY dimmingScope "none" ;
  PROPERTY dimmingIntensity 50 ;
  PROPERTY autoZoomMode "Pan" ;
  PROPERTY autoZoomScale 90 ;
  PROPERTY mergeScope "pcells" ;
END BUFx7

MACRO BUFx8
  CLASS CORE ;
  ORIGIN 0 0 ;
  FOREIGN BUFx8 0 0 ;
  SIZE 0.714 BY 0.12 ;
  SYMMETRY X Y ;
  SITE coreSite ;
  PIN A
    DIRECTION INPUT ;
    USE SIGNAL ;
    PORT
      LAYER M1 ;
        RECT 0.015 0.054 0.321 0.066 ;
        RECT 0.015 0.018 0.027 0.102 ;
    END
  END A
  PIN VDD
    DIRECTION INOUT ;
    USE POWER ;
    SHAPE ABUTMENT ;
    PORT
      LAYER MBPR ;
        RECT -0.009 0.1075 0.723 0.1325 ;
    END
  END VDD
  PIN VSS
    DIRECTION INOUT ;
    USE GROUND ;
    SHAPE ABUTMENT ;
    PORT
      LAYER MBPR ;
        RECT -0.009 -0.0125 0.723 0.0125 ;
    END
  END VSS
  PIN Y
    DIRECTION OUTPUT ;
    USE SIGNAL ;
    PORT
      LAYER M1 ;
        RECT 0.393 0.09 0.699 0.102 ;
        RECT 0.687 0.018 0.699 0.102 ;
        RECT 0.393 0.018 0.699 0.03 ;
    END
  END Y
  OBS
    LAYER M1 ;
      RECT 0.057 0.09 0.363 0.102 ;
      RECT 0.351 0.018 0.363 0.102 ;
      RECT 0.351 0.054 0.657 0.066 ;
      RECT 0.057 0.018 0.363 0.03 ;
    LAYER VBPR ;
      RECT 0.011 -0.006 0.031 0.006 ;
      RECT 0.011 0.114 0.031 0.126 ;
      RECT 0.095 -0.006 0.115 0.006 ;
      RECT 0.095 0.114 0.115 0.126 ;
      RECT 0.179 -0.006 0.199  0.006 ;
      RECT 0.179  0.114 0.199  0.126 ;
      RECT 0.263 -0.006 0.283  0.006 ;
      RECT 0.263  0.114 0.283  0.126 ;
      RECT 0.347 -0.006 0.367  0.006 ;
      RECT 0.347  0.114 0.367  0.126 ;
      RECT 0.431 -0.006 0.451  0.006 ;
      RECT 0.431  0.114 0.451  0.126 ;
      RECT 0.515 -0.006 0.535  0.006 ;
      RECT 0.515  0.114 0.535  0.126 ;
      RECT 0.599 -0.006 0.619  0.006 ;
      RECT 0.599  0.114 0.619  0.126 ;
      RECT 0.683 -0.006 0.703  0.006 ;
      RECT 0.683  0.114 0.703  0.126 ;
  END
  PROPERTY pathCL "yes" ;
  PROPERTY arrayDisplay "Full" ;
  PROPERTY instLabel "master" ;
  PROPERTY startLevel 0 ;
  PROPERTY stopLevel 0 ;
  PROPERTY scrollPercent 25 ;
  PROPERTY gridSpacing 1 ;
  PROPERTY gridMultiple 5 ;
  PROPERTY xSnapSpacing 0.001 ;
  PROPERTY ySnapSpacing 0.001 ;
  PROPERTY snapMode "orthogonal" ;
  PROPERTY segSnapMode "orthogonal" ;
  PROPERTY instanceDrawingMode "BBox" ;
  PROPERTY lppVisibilityMode "donotCheckValidity" ;
  PROPERTY filterSize 6 ;
  PROPERTY filterSizeDrawingStyle "empty" ;
  PROPERTY displayResolution "Medium" ;
  PROPERTY dimmingScope "none" ;
  PROPERTY dimmingIntensity 50 ;
  PROPERTY autoZoomMode "Pan" ;
  PROPERTY autoZoomScale 90 ;
  PROPERTY mergeScope "pcells" ;
END BUFx8

MACRO DFFHQNx1
  CLASS CORE ;
  ORIGIN 0 0 ;
  FOREIGN DFFHQNx1 0 0 ;
  SIZE 0.714 BY 0.12 ;
  SYMMETRY X Y ;
  SITE coreSite ;
  PIN CK
    DIRECTION INPUT ;
    USE SIGNAL ;
    PORT
      LAYER M1 ;
        RECT 0.043 0.018 0.055 0.102 ;
    END
  END CK
  PIN D
    DIRECTION INPUT ;
    USE SIGNAL ;
    PORT
      LAYER M1 ;
        RECT 0.141 0.018 0.153 0.102 ;
    END
  END D
  PIN QN
    DIRECTION OUTPUT ;
    USE SIGNAL ;
    PORT
      LAYER M1 ;
        RECT 0.687 0.018 0.699 0.102 ;
    END
  END QN
  PIN VDD
    DIRECTION INOUT ;
    USE POWER ;
    SHAPE ABUTMENT ;
    PORT
      LAYER MBPR ;
        RECT -0.009 0.1075 0.723 0.1325 ;
    END
  END VDD
  PIN VSS
    DIRECTION INOUT ;
    USE GROUND ;
    SHAPE ABUTMENT ;
    PORT
      LAYER MBPR ;
        RECT -0.009 -0.0125 0.723 0.0125 ;
    END
  END VSS
  OBS
    LAYER M1 ;
      RECT 0.603 0.018 0.615 0.102 ;
      RECT 0.54 0.018 0.615 0.03 ;
      RECT 0.477 0.018 0.489 0.102 ;
      RECT 0.477 0.066 0.573 0.078 ;
      RECT 0.561 0.054 0.573 0.078 ;
      RECT 0.435 0.018 0.489 0.03 ;
      RECT 0.393 0.018 0.405 0.102 ;
      RECT 0.33 0.018 0.405 0.03 ;
      RECT 0.225 0.09 0.279 0.102 ;
      RECT 0.267 0.018 0.279 0.102 ;
      RECT 0.267 0.042 0.363 0.054 ;
      RECT 0.645 0.054 0.657 0.078 ;
      RECT 0.435 0.042 0.447 0.066 ;
      RECT 0.309 0.059 0.321 0.083 ;
      RECT 0.225 0.042 0.237 0.066 ;
      RECT 0.183 0.054 0.195 0.078 ;
      RECT 0.099 0.024 0.111 0.096 ;
      RECT 0.071 0.042 0.083 0.066 ;
      RECT 0.015 0.024 0.027 0.096 ;
    LAYER M2 ;
      RECT 0.561 0.066 0.657 0.078 ;
      RECT 0.015 0.042 0.447 0.054 ;
      RECT 0.099 0.066 0.321 0.078 ;
    LAYER V1 ;
      RECT 0.645 0.066 0.657 0.078 ;
      RECT 0.561 0.066 0.573 0.078 ;
      RECT 0.435 0.042 0.447 0.054 ;
      RECT 0.309 0.066 0.321 0.078 ;
      RECT 0.225 0.042 0.237 0.054 ;
      RECT 0.183 0.066 0.195 0.078 ;
      RECT 0.099 0.066 0.111 0.078 ;
      RECT 0.071 0.042 0.083 0.054 ;
      RECT 0.015 0.042 0.027 0.054 ;
    LAYER VBPR ;
      RECT 0.053 -0.006 0.073 0.006 ;
      RECT 0.053 0.114 0.073 0.126 ;
      RECT 0.137 -0.006 0.157 0.006 ;
      RECT 0.137 0.114 0.157 0.126 ;
      RECT 0.347 -0.006 0.367 0.006 ;
      RECT 0.347 0.114 0.367 0.126 ;
      RECT 0.557 -0.006 0.577 0.006 ;
      RECT 0.557 0.114 0.577 0.126 ;
      RECT 0.641 -0.006 0.661 0.006 ;
      RECT 0.641 0.114 0.661 0.126 ;
  END
END DFFHQNx1

MACRO DFFHx1
  CLASS CORE ;
  ORIGIN 0 0 ;
  FOREIGN DFFHx1 0 0 ;
  SIZE 1.008 BY 0.12 ;
  SYMMETRY X Y ;
  SITE coreSite ;
  PIN CK
    DIRECTION INPUT ;
    USE SIGNAL ;
    PORT
      LAYER M1 ;
        RECT 0.043 0.018 0.055 0.102 ;
    END
  END CK
  PIN D
    DIRECTION INPUT ;
    USE SIGNAL ;
    PORT
      LAYER M1 ;
        RECT 0.141 0.018 0.153 0.102 ;
    END
  END D
  PIN QN
    DIRECTION OUTPUT ;
    USE SIGNAL ;
    PORT
      LAYER M1 ;
        RECT 0.981 0.018 0.993 0.102 ;
    END
  END QN
  PIN RESET
    DIRECTION INPUT ;
    USE SIGNAL ;
    PORT
      LAYER M2 ;
        RECT 0.498 0.09 0.636 0.102 ;
      LAYER M1 ;
        RECT 0.624 0.09 0.72 0.102 ;
        RECT 0.414 0.09 0.51 0.102 ;
      LAYER V1 ;
        RECT 0.498 0.09 0.51 0.102 ;
        RECT 0.624 0.09 0.636 0.102 ;
    END
  END RESET
  PIN SET
    DIRECTION INPUT ;
    USE SIGNAL ;
    PORT
      LAYER M2 ;
        RECT 0.498 0.018 0.636 0.03 ;
      LAYER M1 ;
        RECT 0.624 0.018 0.762 0.03 ;
        RECT 0.456 0.018 0.51 0.03 ;
      LAYER V1 ;
        RECT 0.498 0.018 0.51 0.03 ;
        RECT 0.624 0.018 0.636 0.03 ;
    END
  END SET
  PIN VDD
    DIRECTION INOUT ;
    USE POWER ;
    SHAPE ABUTMENT ;
    PORT
      LAYER MBPR ;
        RECT -0.009 0.1075 1.017 0.1325 ;
    END
  END VDD
  PIN VSS
    DIRECTION INOUT ;
    USE GROUND ;
    SHAPE ABUTMENT ;
    PORT
      LAYER MBPR ;
        RECT -0.009 -0.0125 1.017 0.0125 ;
    END
  END VSS
  OBS
    LAYER M1 ;
      RECT 0.76 0.09 0.909 0.102 ;
      RECT 0.897 0.018 0.909 0.102 ;
      RECT 0.76 0.066 0.772 0.102 ;
      RECT 0.606 0.066 0.772 0.078 ;
      RECT 0.897 0.054 0.951 0.066 ;
      RECT 0.576 0.018 0.588 0.078 ;
      RECT 0.546 0.018 0.588 0.03 ;
      RECT 0.267 0.09 0.363 0.102 ;
      RECT 0.351 0.066 0.363 0.102 ;
      RECT 0.267 0.018 0.279 0.102 ;
      RECT 0.351 0.066 0.489 0.078 ;
      RECT 0.225 0.018 0.279 0.03 ;
      RECT 0.86 0.042 0.872 0.066 ;
      RECT 0.774 0.018 0.867 0.03 ;
      RECT 0.813 0.054 0.825 0.078 ;
      RECT 0.645 0.042 0.783 0.054 ;
      RECT 0.546 0.042 0.558 0.102 ;
      RECT 0.372 0.042 0.528 0.054 ;
      RECT 0.309 0.018 0.405 0.03 ;
      RECT 0.309 0.042 0.321 0.066 ;
      RECT 0.225 0.054 0.237 0.078 ;
      RECT 0.183 0.042 0.195 0.066 ;
      RECT 0.099 0.024 0.111 0.096 ;
      RECT 0.071 0.042 0.083 0.066 ;
      RECT 0.015 0.024 0.027 0.096 ;
    LAYER M2 ;
      RECT 0.015 0.042 0.872 0.054 ;
      RECT 0.099 0.066 0.825 0.078 ;
    LAYER V1 ;
      RECT 0.86 0.042 0.872 0.054 ;
      RECT 0.813 0.066 0.825 0.078 ;
      RECT 0.576 0.066 0.588 0.078 ;
      RECT 0.546 0.042 0.558 0.054 ;
      RECT 0.309 0.042 0.321 0.054 ;
      RECT 0.225 0.066 0.237 0.078 ;
      RECT 0.183 0.042 0.195 0.054 ;
      RECT 0.099 0.066 0.111 0.078 ;
      RECT 0.071 0.042 0.083 0.054 ;
      RECT 0.015 0.042 0.027 0.054 ;
    LAYER VBPR ;
      RECT 0.053 -0.006 0.073 0.006 ;
      RECT 0.053 0.114 0.073 0.126 ;
      RECT 0.137 -0.006 0.157 0.006 ;
      RECT 0.137 0.114 0.157 0.126 ;
      RECT 0.347 -0.006 0.367 0.006 ;
      RECT 0.347 0.114 0.367 0.126 ;
      RECT 0.431 -0.006 0.451 0.006 ;
      RECT 0.431 0.114 0.451 0.126 ;
      RECT 0.515 -0.006 0.535 0.006 ;
      RECT 0.515 0.114 0.535 0.126 ;
      RECT 0.641 -0.006 0.661 0.006 ;
      RECT 0.641 0.114 0.661 0.126 ;
      RECT 0.725 -0.006 0.745 0.006 ;
      RECT 0.725 0.114 0.745 0.126 ;
      RECT 0.809 -0.006 0.829 0.006 ;
      RECT 0.809 0.114 0.829 0.126 ;
      RECT 0.935 -0.006 0.955 0.006 ;
      RECT 0.935 0.114 0.955 0.126 ;
  END
END DFFHx1

MACRO DHLx1
  CLASS CORE ;
  ORIGIN 0 0 ;
  FOREIGN DHLx1 0 0 ;
  SIZE 0.714 BY 0.12 ;
  SYMMETRY X Y ;
  SITE coreSite ;
  PIN CK
    DIRECTION INPUT ;
    USE CLOCK ;
    PORT
      LAYER M1 ;
        RECT 0.043 0.018 0.055 0.102 ;
    END
  END CK
  PIN D
    DIRECTION INPUT ;
    USE SIGNAL ;
    PORT
      LAYER M1 ;
        RECT 0.141 0.018 0.153 0.102 ;
    END
  END D
  PIN Q
    DIRECTION OUTPUT ;
    USE SIGNAL ;
    PORT
      LAYER M1 ;
        RECT 0.477 0.018 0.489 0.102 ;
    END
  END Q
  PIN VDD
    DIRECTION INOUT ;
    USE POWER ;
    SHAPE ABUTMENT ;
    PORT
      LAYER MBPR ;
        RECT -0.009 0.1075 0.723 0.1325 ;
    END
  END VDD
  PIN VSS
    DIRECTION INOUT ;
    USE GROUND ;
    SHAPE ABUTMENT ;
    PORT
      LAYER MBPR ;
        RECT -0.009 -0.0125 0.723 0.0125 ;
    END
  END VSS
  OBS
    LAYER M1 ;
      RECT 0.393 0.018 0.405 0.102 ;
      RECT 0.351 0.042 0.405 0.054 ;
      RECT 0.225 0.09 0.342 0.102 ;
      RECT 0.33 0.066 0.342 0.102 ;
      RECT 0.225 0.024 0.237 0.102 ;
      RECT 0.33 0.066 0.363 0.078 ;
      RECT 0.225 0.024 0.279 0.036 ;
      RECT 0.267 0.066 0.3 0.078 ;
      RECT 0.267 0.054 0.279 0.078 ;
      RECT 0.687 0.018 0.699 0.102 ;
      RECT 0.435 0.054 0.447 0.078 ;
      RECT 0.309 0.03 0.321 0.054 ;
      RECT 0.183 0.042 0.195 0.066 ;
      RECT 0.099 0.024 0.111 0.096 ;
      RECT 0.071 0.042 0.083 0.066 ;
      RECT 0.015 0.024 0.027 0.096 ;
    LAYER M2 ;
      RECT 0.33 0.066 0.447 0.078 ;
      RECT 0.015 0.042 0.321 0.054 ;
      RECT 0.099 0.066 0.279 0.078 ;
    LAYER V1 ;
      RECT 0.435 0.066 0.447 0.078 ;
      RECT 0.33 0.066 0.342 0.078 ;
      RECT 0.309 0.042 0.321 0.054 ;
      RECT 0.267 0.066 0.279 0.078 ;
      RECT 0.183 0.042 0.195 0.054 ;
      RECT 0.099 0.066 0.111 0.078 ;
      RECT 0.071 0.042 0.083 0.054 ;
      RECT 0.015 0.042 0.027 0.054 ;
    LAYER VBPR ;
      RECT 0.053 -0.006 0.073 0.006 ;
      RECT 0.053 0.114 0.073 0.126 ;
      RECT 0.137 -0.006 0.157 0.006 ;
      RECT 0.137 0.114 0.157 0.126 ;
      RECT 0.347 -0.006 0.367 0.006 ;
      RECT 0.347 0.114 0.367 0.126 ;
      RECT 0.431 -0.006 0.451 0.006 ;
      RECT 0.431 0.114 0.451 0.126 ;
  END
END DHLx1

MACRO INVx1
  CLASS CORE ;
  ORIGIN 0 0 ;
  FOREIGN INVx1 0 0 ;
  SIZE 0.084 BY 0.12 ;
  SYMMETRY X Y ;
  SITE coreSite ;
  PIN A
    DIRECTION INPUT ;
    USE SIGNAL ;
    PORT
      LAYER M1 ;
        RECT 0.015 0.018 0.027 0.102 ;
    END
  END A
  PIN VDD
    DIRECTION INOUT ;
    USE POWER ;
    SHAPE ABUTMENT ;
    PORT
      LAYER MBPR ;
        RECT -0.009 0.1075 0.093 0.1325 ;
    END
  END VDD
  PIN VSS
    DIRECTION INOUT ;
    USE GROUND ;
    SHAPE ABUTMENT ;
    PORT
      LAYER MBPR ;
        RECT -0.009 -0.0125 0.093 0.0125 ;
    END
  END VSS
  PIN Y
    DIRECTION OUTPUT ;
    USE SIGNAL ;
    PORT
      LAYER M1 ;
        RECT 0.057 0.018 0.069 0.102 ;
    END
  END Y
  OBS
    LAYER VBPR ;
      RECT 0.011 -0.006 0.031 0.006 ;
      RECT 0.011 0.114 0.031 0.126 ;
  END

  PROPERTY pathCL "yes" ;
  PROPERTY arrayDisplay "Full" ;
  PROPERTY instLabel "master" ;
  PROPERTY startLevel 0 ;
  PROPERTY stopLevel 0 ;
  PROPERTY scrollPercent 25 ;
  PROPERTY gridSpacing 1 ;
  PROPERTY gridMultiple 5 ;
  PROPERTY xSnapSpacing 0.001 ;
  PROPERTY ySnapSpacing 0.001 ;
  PROPERTY snapMode "orthogonal" ;
  PROPERTY segSnapMode "orthogonal" ;
  PROPERTY instanceDrawingMode "BBox" ;
  PROPERTY lppVisibilityMode "donotCheckValidity" ;
  PROPERTY filterSize 6 ;
  PROPERTY filterSizeDrawingStyle "empty" ;
  PROPERTY displayResolution "Medium" ;
  PROPERTY dimmingScope "none" ;
  PROPERTY dimmingIntensity 50 ;
  PROPERTY autoZoomMode "Pan" ;
  PROPERTY autoZoomScale 90 ;
  PROPERTY mergeScope "pcells" ;
END INVx1

MACRO INVx10
  CLASS CORE ;
  ORIGIN 0 0 ;
  FOREIGN INVx10 0 0 ;
  SIZE 0.462 BY 0.12 ;
  SYMMETRY X Y ;
  SITE coreSite ;
  PIN A
    DIRECTION INPUT ;
    USE SIGNAL ;
    PORT
      LAYER M1 ;
        RECT 0.015 0.054 0.405 0.066 ;
        RECT 0.015 0.018 0.027 0.102 ;
    END
  END A
  PIN VDD
    DIRECTION INOUT ;
    USE POWER ;
    SHAPE ABUTMENT ;
    PORT
      LAYER MBPR ;
        RECT -0.009 0.1075 0.471 0.1325 ;
    END
  END VDD
  PIN VSS
    DIRECTION INOUT ;
    USE GROUND ;
    SHAPE ABUTMENT ;
    PORT
      LAYER MBPR ;
        RECT -0.009 -0.0125 0.471 0.0125 ;
    END
  END VSS
  PIN Y
    DIRECTION OUTPUT ;
    USE SIGNAL ;
    PORT
      LAYER M1 ;
        RECT 0.057 0.09 0.447 0.102 ;
        RECT 0.435 0.018 0.447 0.102 ;
        RECT 0.057 0.018 0.447 0.03 ;
    END
  END Y
  OBS
    LAYER VBPR ;
      RECT 0.011 -0.006 0.031 0.006 ;
      RECT 0.011 0.114 0.031 0.126 ;
      RECT 0.095 -0.006 0.115 0.006 ;
      RECT 0.095 0.114 0.115 0.126 ;
      RECT 0.179 -0.006 0.199  0.006 ;
      RECT 0.179  0.114 0.199  0.126 ;
      RECT 0.263 -0.006 0.283  0.006 ;
      RECT 0.263  0.114 0.283  0.126 ;
      RECT 0.347 -0.006 0.367  0.006 ;
      RECT 0.347  0.114 0.367  0.126 ;
      RECT 0.431 -0.006 0.451  0.006 ;
      RECT 0.431  0.114 0.451  0.126 ;
  END
END INVx10

MACRO INVx12
  CLASS CORE ;
  ORIGIN 0 0 ;
  FOREIGN INVx12 0 0 ;
  SIZE 0.546 BY 0.12 ;
  SYMMETRY X Y ;
  SITE coreSite ;
  PIN A
    DIRECTION INPUT ;
    USE SIGNAL ;
    PORT
      LAYER M1 ;
        RECT 0.015 0.054 0.489 0.066 ;
        RECT 0.015 0.018 0.027 0.102 ;
    END
  END A
  PIN VDD
    DIRECTION INOUT ;
    USE POWER ;
    SHAPE ABUTMENT ;
    PORT
      LAYER MBPR ;
        RECT -0.009 0.1075 0.555 0.1325 ;
    END
  END VDD
  PIN VSS
    DIRECTION INOUT ;
    USE GROUND ;
    SHAPE ABUTMENT ;
    PORT
      LAYER MBPR ;
        RECT -0.009 -0.0125 0.555 0.0125 ;
    END
  END VSS
  PIN Y
    DIRECTION OUTPUT ;
    USE SIGNAL ;
    PORT
      LAYER M1 ;
        RECT 0.057 0.09 0.531 0.102 ;
        RECT 0.519 0.018 0.531 0.102 ;
        RECT 0.057 0.018 0.531 0.03 ;
    END
  END Y
  OBS
    LAYER VBPR ;
      RECT 0.011 -0.006 0.031 0.006 ;
      RECT 0.011 0.114 0.031 0.126 ;
      RECT 0.095 -0.006 0.115 0.006 ;
      RECT 0.095 0.114 0.115 0.126 ;
      RECT 0.179 -0.006 0.199  0.006 ;
      RECT 0.179  0.114 0.199  0.126 ;
      RECT 0.263 -0.006 0.283  0.006 ;
      RECT 0.263  0.114 0.283  0.126 ;
      RECT 0.347 -0.006 0.367  0.006 ;
      RECT 0.347  0.114 0.367  0.126 ;
      RECT 0.431 -0.006 0.451  0.006 ;
      RECT 0.431  0.114 0.451  0.126 ;
      RECT 0.515 -0.006 0.535  0.006 ;
      RECT 0.515  0.114 0.535  0.126 ;
  END
END INVx12

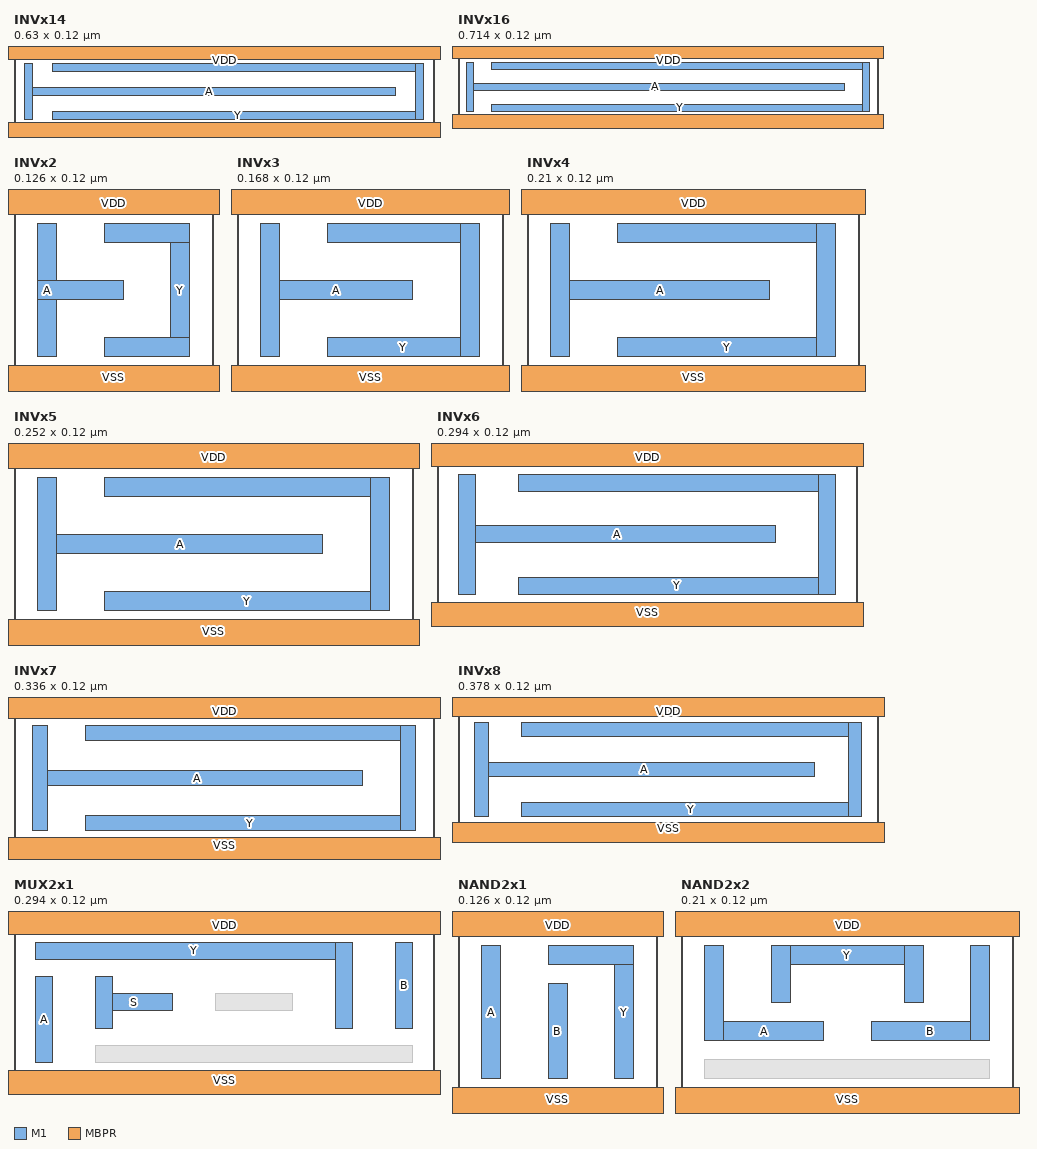
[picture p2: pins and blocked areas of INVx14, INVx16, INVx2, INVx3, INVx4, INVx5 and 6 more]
MACRO INVx14
  CLASS CORE ;
  ORIGIN 0 0 ;
  FOREIGN INVx14 0 0 ;
  SIZE 0.63 BY 0.12 ;
  SYMMETRY X Y ;
  SITE coreSite ;
  PIN A
    DIRECTION INPUT ;
    USE SIGNAL ;
    PORT
      LAYER M1 ;
        RECT 0.015 0.054 0.573 0.066 ;
        RECT 0.015 0.018 0.027 0.102 ;
    END
  END A
  PIN VDD
    DIRECTION INOUT ;
    USE POWER ;
    SHAPE ABUTMENT ;
    PORT
      LAYER MBPR ;
        RECT -0.009 0.1075 0.639 0.1325 ;
    END
  END VDD
  PIN VSS
    DIRECTION INOUT ;
    USE GROUND ;
    SHAPE ABUTMENT ;
    PORT
      LAYER MBPR ;
        RECT -0.009 -0.0125 0.639 0.0125 ;
    END
  END VSS
  PIN Y
    DIRECTION OUTPUT ;
    USE SIGNAL ;
    PORT
      LAYER M1 ;
        RECT 0.057 0.09 0.615 0.102 ;
        RECT 0.603 0.018 0.615 0.102 ;
        RECT 0.057 0.018 0.615 0.03 ;
    END
  END Y
  OBS
    LAYER VBPR ;
      RECT 0.011 -0.006 0.031 0.006 ;
      RECT 0.011 0.114 0.031 0.126 ;
      RECT 0.095 -0.006 0.115 0.006 ;
      RECT 0.095 0.114 0.115 0.126 ;
      RECT 0.179 -0.006 0.199  0.006 ;
      RECT 0.179  0.114 0.199  0.126 ;
      RECT 0.263 -0.006 0.283  0.006 ;
      RECT 0.263  0.114 0.283  0.126 ;
      RECT 0.347 -0.006 0.367  0.006 ;
      RECT 0.347  0.114 0.367  0.126 ;
      RECT 0.431 -0.006 0.451  0.006 ;
      RECT 0.431  0.114 0.451  0.126 ;
      RECT 0.515 -0.006 0.535  0.006 ;
      RECT 0.515  0.114 0.535  0.126 ;
      RECT 0.599 -0.006 0.619  0.006 ;
      RECT 0.599  0.114 0.619  0.126 ;
  END
END INVx14

MACRO INVx16
  CLASS CORE ;
  ORIGIN 0 0 ;
  FOREIGN INVx16 0 0 ;
  SIZE 0.714 BY 0.12 ;
  SYMMETRY X Y ;
  SITE coreSite ;
  PIN A
    DIRECTION INPUT ;
    USE SIGNAL ;
    PORT
      LAYER M1 ;
        RECT 0.015 0.054 0.657 0.066 ;
        RECT 0.015 0.018 0.027 0.102 ;
    END
  END A
  PIN VDD
    DIRECTION INOUT ;
    USE POWER ;
    SHAPE ABUTMENT ;
    PORT
      LAYER MBPR ;
        RECT -0.009 0.1075 0.723 0.1325 ;
    END
  END VDD
  PIN VSS
    DIRECTION INOUT ;
    USE GROUND ;
    SHAPE ABUTMENT ;
    PORT
      LAYER MBPR ;
        RECT -0.009 -0.0125 0.723 0.0125 ;
    END
  END VSS
  PIN Y
    DIRECTION OUTPUT ;
    USE SIGNAL ;
    PORT
      LAYER M1 ;
        RECT 0.057 0.09 0.699 0.102 ;
        RECT 0.687 0.018 0.699 0.102 ;
        RECT 0.057 0.018 0.699 0.03 ;
    END
  END Y
  OBS
    LAYER VBPR ;
      RECT 0.011 -0.006 0.031 0.006 ;
      RECT 0.011 0.114 0.031 0.126 ;
      RECT 0.095 -0.006 0.115 0.006 ;
      RECT 0.095 0.114 0.115 0.126 ;
      RECT 0.179 -0.006 0.199  0.006 ;
      RECT 0.179  0.114 0.199  0.126 ;
      RECT 0.263 -0.006 0.283  0.006 ;
      RECT 0.263  0.114 0.283  0.126 ;
      RECT 0.347 -0.006 0.367  0.006 ;
      RECT 0.347  0.114 0.367  0.126 ;
      RECT 0.431 -0.006 0.451  0.006 ;
      RECT 0.431  0.114 0.451  0.126 ;
      RECT 0.515 -0.006 0.535  0.006 ;
      RECT 0.515  0.114 0.535  0.126 ;
      RECT 0.599 -0.006 0.619  0.006 ;
      RECT 0.599  0.114 0.619  0.126 ;
      RECT 0.683 -0.006 0.703  0.006 ;
      RECT 0.683  0.114 0.703  0.126 ;
  END
END INVx16

MACRO INVx2
  CLASS CORE ;
  ORIGIN 0 0 ;
  FOREIGN INVx2 0 0 ;
  SIZE 0.126 BY 0.12 ;
  SYMMETRY X Y ;
  SITE coreSite ;
  PIN A
    DIRECTION INPUT ;
    USE SIGNAL ;
    PORT
      LAYER M1 ;
        RECT 0.015 0.054 0.069 0.066 ;
        RECT 0.015 0.018 0.027 0.102 ;
    END
  END A
  PIN VDD
    DIRECTION INOUT ;
    USE POWER ;
    SHAPE ABUTMENT ;
    PORT
      LAYER MBPR ;
        RECT -0.009 0.1075 0.135 0.1325 ;
    END
  END VDD
  PIN VSS
    DIRECTION INOUT ;
    USE GROUND ;
    SHAPE ABUTMENT ;
    PORT
      LAYER MBPR ;
        RECT -0.009 -0.0125 0.135 0.0125 ;
    END
  END VSS
  PIN Y
    DIRECTION OUTPUT ;
    USE SIGNAL ;
    PORT
      LAYER M1 ;
        RECT 0.057 0.09 0.111 0.102 ;
        RECT 0.099 0.018 0.111 0.102 ;
        RECT 0.057 0.018 0.111 0.03 ;
    END
  END Y
  OBS
    LAYER VBPR ;
      RECT 0.011 -0.006 0.031 0.006 ;
      RECT 0.011 0.114 0.031 0.126 ;
      RECT 0.095 -0.006 0.115 0.006 ;
      RECT 0.095 0.114 0.115 0.126 ;
  END
END INVx2

MACRO INVx3
  CLASS CORE ;
  ORIGIN 0 0 ;
  FOREIGN INVx3 0 0 ;
  SIZE 0.168 BY 0.12 ;
  SYMMETRY X Y ;
  SITE coreSite ;
  PIN A
    DIRECTION INPUT ;
    USE SIGNAL ;
    PORT
      LAYER M1 ;
        RECT 0.015 0.054 0.111 0.066 ;
        RECT 0.015 0.018 0.027 0.102 ;
    END
  END A
  PIN VDD
    DIRECTION INOUT ;
    USE POWER ;
    SHAPE ABUTMENT ;
    PORT
      LAYER MBPR ;
        RECT -0.009 0.1075 0.177 0.1325 ;
    END
  END VDD
  PIN VSS
    DIRECTION INOUT ;
    USE GROUND ;
    SHAPE ABUTMENT ;
    PORT
      LAYER MBPR ;
        RECT -0.009 -0.0125 0.177 0.0125 ;
    END
  END VSS
  PIN Y
    DIRECTION OUTPUT ;
    USE SIGNAL ;
    PORT
      LAYER M1 ;
        RECT 0.057 0.09 0.153 0.102 ;
        RECT 0.141 0.018 0.153 0.102 ;
        RECT 0.057 0.018 0.153 0.03 ;
    END
  END Y
  OBS
    LAYER VBPR ;
      RECT 0.011 -0.006 0.031 0.006 ;
      RECT 0.011 0.114 0.031 0.126 ;
      RECT 0.095 -0.006 0.115 0.006 ;
      RECT 0.095 0.114 0.115 0.126 ;
  END
END INVx3

MACRO INVx4
  CLASS CORE ;
  ORIGIN 0 0 ;
  FOREIGN INVx4 0 0 ;
  SIZE 0.21 BY 0.12 ;
  SYMMETRY X Y ;
  SITE coreSite ;
  PIN A
    DIRECTION INPUT ;
    USE SIGNAL ;
    PORT
      LAYER M1 ;
        RECT 0.015 0.054 0.153 0.066 ;
        RECT 0.015 0.018 0.027 0.102 ;
    END
  END A
  PIN VDD
    DIRECTION INOUT ;
    USE POWER ;
    SHAPE ABUTMENT ;
    PORT
      LAYER MBPR ;
        RECT -0.009 0.1075 0.219 0.1325 ;
    END
  END VDD
  PIN VSS
    DIRECTION INOUT ;
    USE GROUND ;
    SHAPE ABUTMENT ;
    PORT
      LAYER MBPR ;
        RECT -0.009 -0.0125 0.219 0.0125 ;
    END
  END VSS
  PIN Y
    DIRECTION OUTPUT ;
    USE SIGNAL ;
    PORT
      LAYER M1 ;
        RECT 0.057 0.09 0.195 0.102 ;
        RECT 0.183 0.018 0.195 0.102 ;
        RECT 0.057 0.018 0.195 0.03 ;
    END
  END Y
  OBS
    LAYER VBPR ;
      RECT 0.011 -0.006 0.031 0.006 ;
      RECT 0.011 0.114 0.031 0.126 ;
      RECT 0.095 -0.006 0.115 0.006 ;
      RECT 0.095 0.114 0.115 0.126 ;
      RECT 0.179 -0.006 0.199  0.006 ;
      RECT 0.179  0.114 0.199  0.126 ;
  END
END INVx4

MACRO INVx5
  CLASS CORE ;
  ORIGIN 0 0 ;
  FOREIGN INVx5 0 0 ;
  SIZE 0.252 BY 0.12 ;
  SYMMETRY X Y ;
  SITE coreSite ;
  PIN A
    DIRECTION INPUT ;
    USE SIGNAL ;
    PORT
      LAYER M1 ;
        RECT 0.015 0.054 0.195 0.066 ;
        RECT 0.015 0.018 0.027 0.102 ;
    END
  END A
  PIN VDD
    DIRECTION INOUT ;
    USE POWER ;
    SHAPE ABUTMENT ;
    PORT
      LAYER MBPR ;
        RECT -0.009 0.1075 0.261 0.1325 ;
    END
  END VDD
  PIN VSS
    DIRECTION INOUT ;
    USE GROUND ;
    SHAPE ABUTMENT ;
    PORT
      LAYER MBPR ;
        RECT -0.009 -0.0125 0.261 0.0125 ;
    END
  END VSS
  PIN Y
    DIRECTION OUTPUT ;
    USE SIGNAL ;
    PORT
      LAYER M1 ;
        RECT 0.057 0.09 0.237 0.102 ;
        RECT 0.225 0.018 0.237 0.102 ;
        RECT 0.057 0.018 0.237 0.03 ;
    END
  END Y
  OBS
    LAYER VBPR ;
      RECT 0.011 -0.006 0.031 0.006 ;
      RECT 0.011 0.114 0.031 0.126 ;
      RECT 0.095 -0.006 0.115 0.006 ;
      RECT 0.095 0.114 0.115 0.126 ;
      RECT 0.179 -0.006 0.199  0.006 ;
      RECT 0.179  0.114 0.199  0.126 ;
  END
END INVx5

MACRO INVx6
  CLASS CORE ;
  ORIGIN 0 0 ;
  FOREIGN INVx6 0 0 ;
  SIZE 0.294 BY 0.12 ;
  SYMMETRY X Y ;
  SITE coreSite ;
  PIN A
    DIRECTION INPUT ;
    USE SIGNAL ;
    PORT
      LAYER M1 ;
        RECT 0.015 0.054 0.237 0.066 ;
        RECT 0.015 0.018 0.027 0.102 ;
    END
  END A
  PIN VDD
    DIRECTION INOUT ;
    USE POWER ;
    SHAPE ABUTMENT ;
    PORT
      LAYER MBPR ;
        RECT -0.009 0.1075 0.303 0.1325 ;
    END
  END VDD
  PIN VSS
    DIRECTION INOUT ;
    USE GROUND ;
    SHAPE ABUTMENT ;
    PORT
      LAYER MBPR ;
        RECT -0.009 -0.0125 0.303 0.0125 ;
    END
  END VSS
  PIN Y
    DIRECTION OUTPUT ;
    USE SIGNAL ;
    PORT
      LAYER M1 ;
        RECT 0.057 0.09 0.279 0.102 ;
        RECT 0.267 0.018 0.279 0.102 ;
        RECT 0.057 0.018 0.279 0.03 ;
    END
  END Y
  OBS
    LAYER VBPR ;
      RECT 0.011 -0.006 0.031 0.006 ;
      RECT 0.011 0.114 0.031 0.126 ;
      RECT 0.095 -0.006 0.115 0.006 ;
      RECT 0.095 0.114 0.115 0.126 ;
      RECT 0.179 -0.006 0.199  0.006 ;
      RECT 0.179  0.114 0.199  0.126 ;
      RECT 0.263 -0.006 0.283  0.006 ;
      RECT 0.263  0.114 0.283  0.126 ;
  END
END INVx6

MACRO INVx7
  CLASS CORE ;
  ORIGIN 0 0 ;
  FOREIGN INVx7 0 0 ;
  SIZE 0.336 BY 0.12 ;
  SYMMETRY X Y ;
  SITE coreSite ;
  PIN A
    DIRECTION INPUT ;
    USE SIGNAL ;
    PORT
      LAYER M1 ;
        RECT 0.015 0.054 0.279 0.066 ;
        RECT 0.015 0.018 0.027 0.102 ;
    END
  END A
  PIN VDD
    DIRECTION INOUT ;
    USE POWER ;
    SHAPE ABUTMENT ;
    PORT
      LAYER MBPR ;
        RECT -0.009 0.1075 0.345 0.1325 ;
    END
  END VDD
  PIN VSS
    DIRECTION INOUT ;
    USE GROUND ;
    SHAPE ABUTMENT ;
    PORT
      LAYER MBPR ;
        RECT -0.009 -0.0125 0.345 0.0125 ;
    END
  END VSS
  PIN Y
    DIRECTION OUTPUT ;
    USE SIGNAL ;
    PORT
      LAYER M1 ;
        RECT 0.057 0.09 0.321 0.102 ;
        RECT 0.309 0.018 0.321 0.102 ;
        RECT 0.057 0.018 0.321 0.03 ;
    END
  END Y
  OBS
    LAYER VBPR ;
      RECT 0.011 -0.006 0.031 0.006 ;
      RECT 0.011 0.114 0.031 0.126 ;
      RECT 0.095 -0.006 0.115 0.006 ;
      RECT 0.095 0.114 0.115 0.126 ;
      RECT 0.179 -0.006 0.199  0.006 ;
      RECT 0.179  0.114 0.199  0.126 ;
      RECT 0.263 -0.006 0.283  0.006 ;
      RECT 0.263  0.114 0.283  0.126 ;
  END
END INVx7

MACRO INVx8
  CLASS CORE ;
  ORIGIN 0 0 ;
  FOREIGN INVx8 0 0 ;
  SIZE 0.378 BY 0.12 ;
  SYMMETRY X Y ;
  SITE coreSite ;
  PIN A
    DIRECTION INPUT ;
    USE SIGNAL ;
    PORT
      LAYER M1 ;
        RECT 0.015 0.054 0.321 0.066 ;
        RECT 0.015 0.018 0.027 0.102 ;
    END
  END A
  PIN VDD
    DIRECTION INOUT ;
    USE POWER ;
    SHAPE ABUTMENT ;
    PORT
      LAYER MBPR ;
        RECT -0.009 0.1075 0.387 0.1325 ;
    END
  END VDD
  PIN VSS
    DIRECTION INOUT ;
    USE GROUND ;
    SHAPE ABUTMENT ;
    PORT
      LAYER MBPR ;
        RECT -0.009 -0.0125 0.387 0.0125 ;
    END
  END VSS
  PIN Y
    DIRECTION OUTPUT ;
    USE SIGNAL ;
    PORT
      LAYER M1 ;
        RECT 0.057 0.09 0.363 0.102 ;
        RECT 0.351 0.018 0.363 0.102 ;
        RECT 0.057 0.018 0.363 0.03 ;
    END
  END Y
  OBS
    LAYER VBPR ;
      RECT 0.011 -0.006 0.031 0.006 ;
      RECT 0.011 0.114 0.031 0.126 ;
      RECT 0.095 -0.006 0.115 0.006 ;
      RECT 0.095 0.114 0.115 0.126 ;
      RECT 0.179 -0.006 0.199  0.006 ;
      RECT 0.179  0.114 0.199  0.126 ;
      RECT 0.263 -0.006 0.283  0.006 ;
      RECT 0.263  0.114 0.283  0.126 ;
      RECT 0.347 -0.006 0.367  0.006 ;
      RECT 0.347  0.114 0.367  0.126 ;
  END
END INVx8

MACRO MUX2x1
  CLASS CORE ;
  ORIGIN 0 0 ;
  FOREIGN MUX2x1 0 0 ;
  SIZE 0.294 BY 0.12 ;
  SYMMETRY X Y ;
  SITE coreSite ;
  PIN A
    DIRECTION INPUT ;
    USE SIGNAL ;
    PORT
      LAYER M1 ;
        RECT 0.015 0.018 0.027 0.078 ;
    END
  END A
  PIN B
    DIRECTION INPUT ;
    USE SIGNAL ;
    PORT
      LAYER M1 ;
        RECT 0.267 0.042 0.279 0.102 ;
    END
  END B
  PIN S
    DIRECTION INPUT ;
    USE SIGNAL ;
    PORT
      LAYER M1 ;
        RECT 0.057 0.054 0.111 0.066 ;
        RECT 0.057 0.042 0.069 0.078 ;
    END
  END S
  PIN VDD
    DIRECTION INOUT ;
    USE POWER ;
    SHAPE ABUTMENT ;
    PORT
      LAYER MBPR ;
        RECT -0.009 0.1075 0.303 0.1325 ;
    END
  END VDD
  PIN VSS
    DIRECTION INOUT ;
    USE GROUND ;
    SHAPE ABUTMENT ;
    PORT
      LAYER MBPR ;
        RECT -0.009 -0.0125 0.303 0.0125 ;
    END
  END VSS
  PIN Y
    DIRECTION OUTPUT ;
    USE SIGNAL ;
    PORT
      LAYER M1 ;
        RECT 0.015 0.09 0.237 0.102 ;
        RECT 0.225 0.042 0.237 0.102 ;
    END
  END Y
  OBS
    LAYER M1 ;
      RECT 0.057 0.018 0.279 0.03 ;
      RECT 0.141 0.054 0.195 0.066 ;
    LAYER VBPR ;
      RECT 0.011 -0.006 0.031 0.006 ;
      RECT 0.095 -0.006 0.115 0.006 ;
      RECT 0.095 0.114 0.115 0.126 ;
      RECT 0.263 0.114 0.283 0.126 ;
  END
END MUX2x1

MACRO NAND2x1
  CLASS CORE ;
  ORIGIN 0 0 ;
  FOREIGN NAND2x1 0 0 ;
  SIZE 0.126 BY 0.12 ;
  SYMMETRY X Y ;
  SITE coreSite ;
  PIN A
    DIRECTION INPUT ;
    USE SIGNAL ;
    PORT
      LAYER M1 ;
        RECT 0.015 0.018 0.027 0.102 ;
    END
  END A
  PIN B
    DIRECTION INPUT ;
    USE SIGNAL ;
    PORT
      LAYER M1 ;
        RECT 0.057 0.018 0.069 0.078 ;
    END
  END B
  PIN VDD
    DIRECTION INOUT ;
    USE POWER ;
    SHAPE ABUTMENT ;
    PORT
      LAYER MBPR ;
        RECT -0.009 0.1075 0.135 0.1325 ;
    END
  END VDD
  PIN VSS
    DIRECTION INOUT ;
    USE GROUND ;
    SHAPE ABUTMENT ;
    PORT
      LAYER MBPR ;
        RECT -0.009 -0.0125 0.135 0.0125 ;
    END
  END VSS
  PIN Y
    DIRECTION OUTPUT ;
    USE SIGNAL ;
    PORT
      LAYER M1 ;
        RECT 0.057 0.09 0.111 0.102 ;
        RECT 0.099 0.018 0.111 0.102 ;
    END
  END Y
  OBS
    LAYER VBPR ;
      RECT 0.011 -0.006 0.031 0.006 ;
      RECT 0.011 0.114 0.031 0.126 ;
      RECT 0.095 0.114 0.115 0.126 ;
  END
END NAND2x1

MACRO NAND2x2
  CLASS CORE ;
  ORIGIN 0 0 ;
  FOREIGN NAND2x2 0 0 ;
  SIZE 0.21 BY 0.12 ;
  SYMMETRY X Y ;
  SITE coreSite ;
  PIN A
    DIRECTION INPUT ;
    USE SIGNAL ;
    PORT
      LAYER M1 ;
        RECT 0.015 0.042 0.09 0.054 ;
        RECT 0.015 0.042 0.027 0.102 ;
    END
  END A
  PIN B
    DIRECTION INPUT ;
    USE SIGNAL ;
    PORT
      LAYER M1 ;
        RECT 0.183 0.042 0.195 0.102 ;
        RECT 0.12 0.042 0.195 0.054 ;
    END
  END B
  PIN VDD
    DIRECTION INOUT ;
    USE POWER ;
    SHAPE ABUTMENT ;
    PORT
      LAYER MBPR ;
        RECT -0.009 0.1075 0.219 0.1325 ;
    END
  END VDD
  PIN VSS
    DIRECTION INOUT ;
    USE GROUND ;
    SHAPE ABUTMENT ;
    PORT
      LAYER MBPR ;
        RECT -0.009 -0.0125 0.219 0.0125 ;
    END
  END VSS
  PIN Y
    DIRECTION OUTPUT ;
    USE SIGNAL ;
    PORT
      LAYER M1 ;
        RECT 0.057 0.09 0.153 0.102 ;
        RECT 0.141 0.066 0.153 0.102 ;
        RECT 0.057 0.066 0.069 0.102 ;
    END
  END Y
  OBS
    LAYER M1 ;
      RECT 0.015 0.018 0.195 0.03 ;
    LAYER VBPR ;
      RECT 0.053 -0.006 0.073 0.006 ;
      RECT 0.011 0.114 0.031 0.126 ;
      RECT 0.095 0.114 0.115 0.126 ;
  END
END NAND2x2

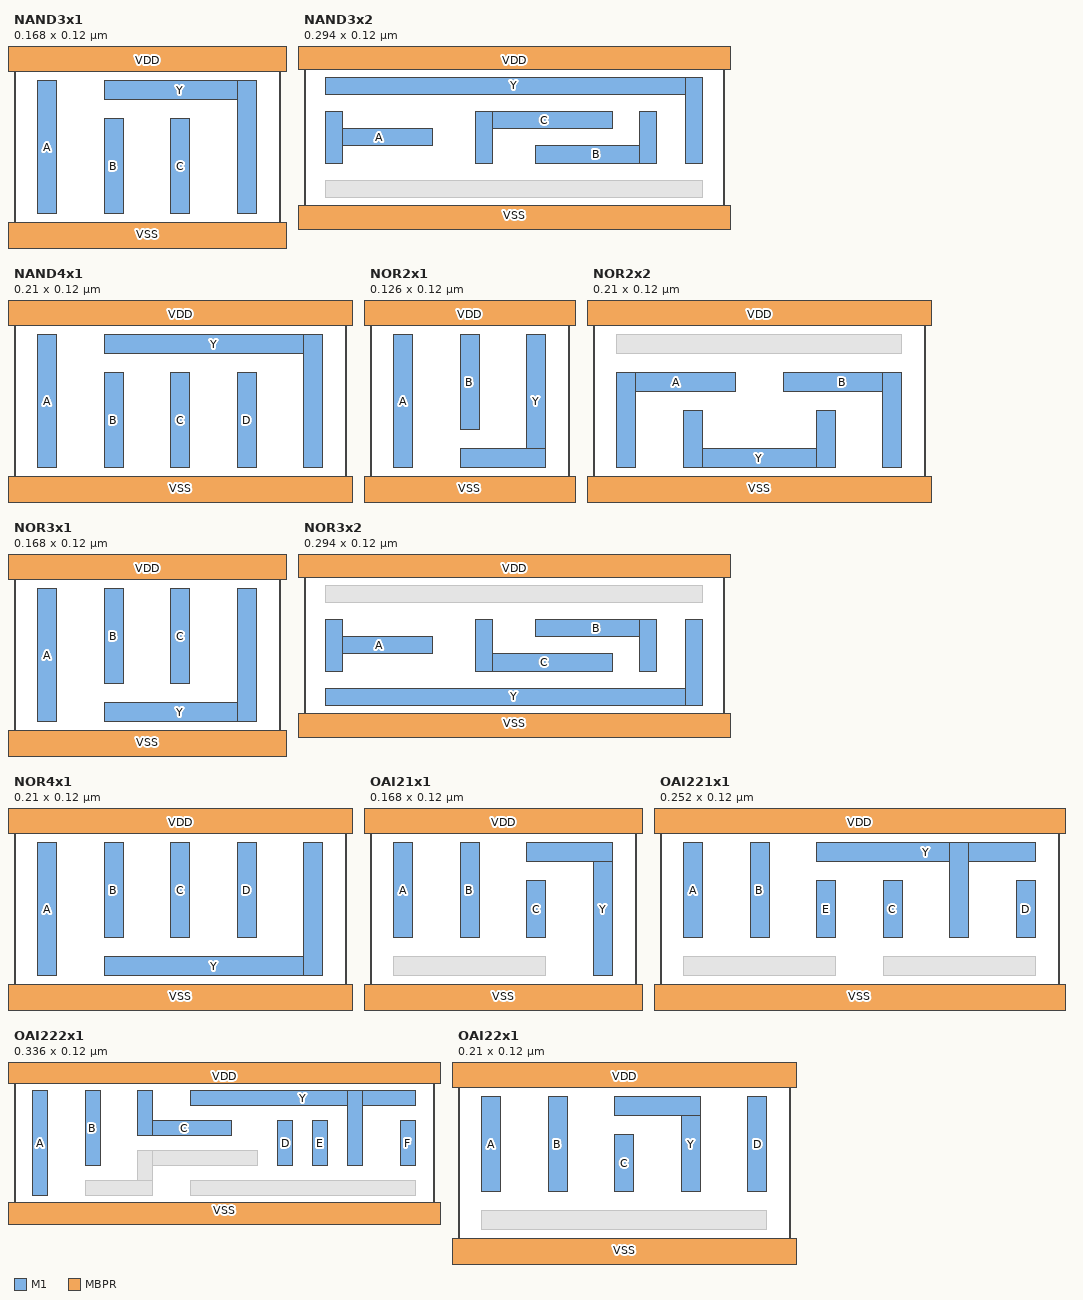
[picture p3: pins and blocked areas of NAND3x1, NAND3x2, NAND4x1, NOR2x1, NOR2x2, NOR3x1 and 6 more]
MACRO NAND3x1
  CLASS CORE ;
  ORIGIN 0 0 ;
  FOREIGN NAND3x1 0 0 ;
  SIZE 0.168 BY 0.12 ;
  SYMMETRY X Y ;
  SITE coreSite ;
  PIN A
    DIRECTION INPUT ;
    USE SIGNAL ;
    PORT
      LAYER M1 ;
        RECT 0.015 0.018 0.027 0.102 ;
    END
  END A
  PIN B
    DIRECTION INPUT ;
    USE SIGNAL ;
    PORT
      LAYER M1 ;
        RECT 0.057 0.018 0.069 0.078 ;
    END
  END B
  PIN C
    DIRECTION INPUT ;
    USE SIGNAL ;
    PORT
      LAYER M1 ;
        RECT 0.099 0.018 0.111 0.078 ;
    END
  END C
  PIN VDD
    DIRECTION INOUT ;
    USE POWER ;
    SHAPE ABUTMENT ;
    PORT
      LAYER MBPR ;
        RECT -0.009 0.1075 0.177 0.1325 ;
    END
  END VDD
  PIN VSS
    DIRECTION INOUT ;
    USE GROUND ;
    SHAPE ABUTMENT ;
    PORT
      LAYER MBPR ;
        RECT -0.009 -0.0125 0.177 0.0125 ;
    END
  END VSS
  PIN Y
    DIRECTION OUTPUT ;
    USE SIGNAL ;
    PORT
      LAYER M1 ;
        RECT 0.057 0.09 0.153 0.102 ;
        RECT 0.141 0.018 0.153 0.102 ;
    END
  END Y
  OBS
    LAYER VBPR ;
      RECT 0.011 -0.006 0.031 0.006 ;
      RECT 0.011 0.114 0.031 0.126 ;
      RECT 0.095 0.114 0.115 0.126 ;
  END
END NAND3x1

MACRO NAND3x2
  CLASS CORE ;
  ORIGIN 0 0 ;
  FOREIGN NAND3x2 0 0 ;
  SIZE 0.294 BY 0.12 ;
  SYMMETRY X Y ;
  SITE coreSite ;
  PIN A
    DIRECTION INPUT ;
    USE SIGNAL ;
    PORT
      LAYER M1 ;
        RECT 0.015 0.054 0.09 0.066 ;
        RECT 0.015 0.042 0.027 0.078 ;
    END
  END A
  PIN B
    DIRECTION INPUT ;
    USE SIGNAL ;
    PORT
      LAYER M1 ;
        RECT 0.235 0.042 0.247 0.078 ;
        RECT 0.162 0.042 0.247 0.054 ;
    END
  END B
  PIN C
    DIRECTION INPUT ;
    USE SIGNAL ;
    PORT
      LAYER M1 ;
        RECT 0.12 0.066 0.216 0.078 ;
        RECT 0.12 0.042 0.132 0.078 ;
    END
  END C
  PIN VDD
    DIRECTION INOUT ;
    USE POWER ;
    SHAPE ABUTMENT ;
    PORT
      LAYER MBPR ;
        RECT -0.009 0.1075 0.303 0.1325 ;
    END
  END VDD
  PIN VSS
    DIRECTION INOUT ;
    USE GROUND ;
    SHAPE ABUTMENT ;
    PORT
      LAYER MBPR ;
        RECT -0.009 -0.0125 0.303 0.0125 ;
    END
  END VSS
  PIN Y
    DIRECTION OUTPUT ;
    USE SIGNAL ;
    PORT
      LAYER M1 ;
        RECT 0.015 0.09 0.279 0.102 ;
        RECT 0.267 0.042 0.279 0.102 ;
    END
  END Y
  OBS
    LAYER M1 ;
      RECT 0.015 0.018 0.279 0.03 ;
    LAYER VBPR ;
      RECT 0.053 -0.006 0.073 0.006 ;
      RECT 0.053 0.114 0.073 0.126 ;
      RECT 0.137 0.114 0.157 0.126 ;
      RECT 0.221 0.114 0.241 0.126 ;
  END
END NAND3x2

MACRO NAND4x1
  CLASS CORE ;
  ORIGIN 0 0 ;
  FOREIGN NAND4x1 0 0 ;
  SIZE 0.21 BY 0.12 ;
  SYMMETRY X Y ;
  SITE coreSite ;
  PIN A
    DIRECTION INPUT ;
    USE SIGNAL ;
    PORT
      LAYER M1 ;
        RECT 0.015 0.018 0.027 0.102 ;
    END
  END A
  PIN B
    DIRECTION INPUT ;
    USE SIGNAL ;
    PORT
      LAYER M1 ;
        RECT 0.057 0.018 0.069 0.078 ;
    END
  END B
  PIN C
    DIRECTION INPUT ;
    USE SIGNAL ;
    PORT
      LAYER M1 ;
        RECT 0.099 0.018 0.111 0.078 ;
    END
  END C
  PIN D
    DIRECTION INPUT ;
    USE SIGNAL ;
    PORT
      LAYER M1 ;
        RECT 0.141 0.018 0.153 0.078 ;
    END
  END D
  PIN VDD
    DIRECTION INOUT ;
    USE POWER ;
    SHAPE ABUTMENT ;
    PORT
      LAYER MBPR ;
        RECT -0.009 0.1075 0.219 0.1325 ;
    END
  END VDD
  PIN VSS
    DIRECTION INOUT ;
    USE GROUND ;
    SHAPE ABUTMENT ;
    PORT
      LAYER MBPR ;
        RECT -0.009 -0.0125 0.219 0.0125 ;
    END
  END VSS
  PIN Y
    DIRECTION OUTPUT ;
    USE SIGNAL ;
    PORT
      LAYER M1 ;
        RECT 0.057 0.09 0.195 0.102 ;
        RECT 0.183 0.018 0.195 0.102 ;
    END
  END Y
  OBS
    LAYER VBPR ;
      RECT 0.011 -0.006 0.031 0.006 ;
      RECT 0.011 0.114 0.031 0.126 ;
      RECT 0.095 0.114 0.115 0.126 ;
      RECT 0.179 0.114 0.199 0.126 ;
  END
END NAND4x1

MACRO NOR2x1
  CLASS CORE ;
  ORIGIN 0 0 ;
  FOREIGN NOR2x1 0 0 ;
  SIZE 0.126 BY 0.12 ;
  SYMMETRY X Y ;
  SITE coreSite ;
  PIN A
    DIRECTION INPUT ;
    USE SIGNAL ;
    PORT
      LAYER M1 ;
        RECT 0.015 0.018 0.027 0.102 ;
    END
  END A
  PIN B
    DIRECTION INPUT ;
    USE SIGNAL ;
    PORT
      LAYER M1 ;
        RECT 0.057 0.042 0.069 0.102 ;
    END
  END B
  PIN VDD
    DIRECTION INOUT ;
    USE POWER ;
    SHAPE ABUTMENT ;
    PORT
      LAYER MBPR ;
        RECT -0.009 0.1075 0.135 0.1325 ;
    END
  END VDD
  PIN VSS
    DIRECTION INOUT ;
    USE GROUND ;
    SHAPE ABUTMENT ;
    PORT
      LAYER MBPR ;
        RECT -0.009 -0.0125 0.135 0.0125 ;
    END
  END VSS
  PIN Y
    DIRECTION OUTPUT ;
    USE SIGNAL ;
    PORT
      LAYER M1 ;
        RECT 0.099 0.018 0.111 0.102 ;
        RECT 0.057 0.018 0.111 0.03 ;
    END
  END Y
  OBS
    LAYER VBPR ;
      RECT 0.011 -0.006 0.031 0.006 ;
      RECT 0.011 0.114 0.031 0.126 ;
      RECT 0.095 -0.006 0.115 0.006 ;
  END
END NOR2x1

MACRO NOR2x2
  CLASS CORE ;
  ORIGIN 0 0 ;
  FOREIGN NOR2x2 0 0 ;
  SIZE 0.21 BY 0.12 ;
  SYMMETRY X Y ;
  SITE coreSite ;
  PIN A
    DIRECTION INPUT ;
    USE SIGNAL ;
    PORT
      LAYER M1 ;
        RECT 0.015 0.066 0.09 0.078 ;
        RECT 0.015 0.018 0.027 0.078 ;
    END
  END A
  PIN B
    DIRECTION INPUT ;
    USE SIGNAL ;
    PORT
      LAYER M1 ;
        RECT 0.12 0.066 0.195 0.078 ;
        RECT 0.183 0.018 0.195 0.078 ;
    END
  END B
  PIN VDD
    DIRECTION INOUT ;
    USE POWER ;
    SHAPE ABUTMENT ;
    PORT
      LAYER MBPR ;
        RECT -0.009 0.1075 0.219 0.1325 ;
    END
  END VDD
  PIN VSS
    DIRECTION INOUT ;
    USE GROUND ;
    SHAPE ABUTMENT ;
    PORT
      LAYER MBPR ;
        RECT -0.009 -0.0125 0.219 0.0125 ;
    END
  END VSS
  PIN Y
    DIRECTION OUTPUT ;
    USE SIGNAL ;
    PORT
      LAYER M1 ;
        RECT 0.141 0.018 0.153 0.054 ;
        RECT 0.057 0.018 0.153 0.03 ;
        RECT 0.057 0.018 0.069 0.054 ;
    END
  END Y
  OBS
    LAYER M1 ;
      RECT 0.015 0.09 0.195 0.102 ;
    LAYER VBPR ;
      RECT 0.011 -0.006 0.031 0.006 ;
      RECT 0.053 0.114 0.073 0.126 ;
      RECT 0.095 -0.006 0.115 0.006 ;
      RECT 0.179 -0.006 0.199 0.006 ;
  END
END NOR2x2

MACRO NOR3x1
  CLASS CORE ;
  ORIGIN 0 0 ;
  FOREIGN NOR3x1 0 0 ;
  SIZE 0.168 BY 0.12 ;
  SYMMETRY X Y ;
  SITE coreSite ;
  PIN A
    DIRECTION INPUT ;
    USE SIGNAL ;
    PORT
      LAYER M1 ;
        RECT 0.015 0.018 0.027 0.102 ;
    END
  END A
  PIN B
    DIRECTION INPUT ;
    USE SIGNAL ;
    PORT
      LAYER M1 ;
        RECT 0.057 0.042 0.069 0.102 ;
    END
  END B
  PIN C
    DIRECTION INPUT ;
    USE SIGNAL ;
    PORT
      LAYER M1 ;
        RECT 0.099 0.042 0.111 0.102 ;
    END
  END C
  PIN VDD
    DIRECTION INOUT ;
    USE POWER ;
    SHAPE ABUTMENT ;
    PORT
      LAYER MBPR ;
        RECT -0.009 0.1075 0.177 0.1325 ;
    END
  END VDD
  PIN VSS
    DIRECTION INOUT ;
    USE GROUND ;
    SHAPE ABUTMENT ;
    PORT
      LAYER MBPR ;
        RECT -0.009 -0.0125 0.177 0.0125 ;
    END
  END VSS
  PIN Y
    DIRECTION OUTPUT ;
    USE SIGNAL ;
    PORT
      LAYER M1 ;
        RECT 0.141 0.018 0.153 0.102 ;
        RECT 0.057 0.018 0.153 0.03 ;
    END
  END Y
  OBS
    LAYER VBPR ;
      RECT 0.011 -0.006 0.031 0.006 ;
      RECT 0.011 0.114 0.031 0.126 ;
      RECT 0.095 -0.006 0.115 0.006 ;
  END
END NOR3x1

MACRO NOR3x2
  CLASS CORE ;
  ORIGIN 0 0 ;
  FOREIGN NOR3x2 0 0 ;
  SIZE 0.294 BY 0.12 ;
  SYMMETRY X Y ;
  SITE coreSite ;
  PIN A
    DIRECTION INPUT ;
    USE SIGNAL ;
    PORT
      LAYER M1 ;
        RECT 0.015 0.054 0.09 0.066 ;
        RECT 0.015 0.042 0.027 0.078 ;
    END
  END A
  PIN B
    DIRECTION INPUT ;
    USE SIGNAL ;
    PORT
      LAYER M1 ;
        RECT 0.162 0.066 0.247 0.078 ;
        RECT 0.235 0.042 0.247 0.078 ;
    END
  END B
  PIN C
    DIRECTION INPUT ;
    USE SIGNAL ;
    PORT
      LAYER M1 ;
        RECT 0.12 0.042 0.216 0.054 ;
        RECT 0.12 0.042 0.132 0.078 ;
    END
  END C
  PIN VDD
    DIRECTION INOUT ;
    USE POWER ;
    SHAPE ABUTMENT ;
    PORT
      LAYER MBPR ;
        RECT -0.009 0.1075 0.303 0.1325 ;
    END
  END VDD
  PIN VSS
    DIRECTION INOUT ;
    USE GROUND ;
    SHAPE ABUTMENT ;
    PORT
      LAYER MBPR ;
        RECT -0.009 -0.0125 0.303 0.0125 ;
    END
  END VSS
  PIN Y
    DIRECTION OUTPUT ;
    USE SIGNAL ;
    PORT
      LAYER M1 ;
        RECT 0.267 0.018 0.279 0.078 ;
        RECT 0.015 0.018 0.279 0.03 ;
    END
  END Y
  OBS
    LAYER M1 ;
      RECT 0.015 0.09 0.279 0.102 ;
    LAYER VBPR ;
      RECT 0.053 -0.006 0.073 0.006 ;
      RECT 0.053 0.114 0.073 0.126 ;
      RECT 0.137 -0.006 0.157 0.006 ;
      RECT 0.221 -0.006 0.251 0.006 ;
  END
END NOR3x2

MACRO NOR4x1
  CLASS CORE ;
  ORIGIN 0 0 ;
  FOREIGN NOR4x1 0 0 ;
  SIZE 0.21 BY 0.12 ;
  SYMMETRY X Y ;
  SITE coreSite ;
  PIN A
    DIRECTION INPUT ;
    USE SIGNAL ;
    PORT
      LAYER M1 ;
        RECT 0.015 0.018 0.027 0.102 ;
    END
  END A
  PIN B
    DIRECTION INPUT ;
    USE SIGNAL ;
    PORT
      LAYER M1 ;
        RECT 0.057 0.042 0.069 0.102 ;
    END
  END B
  PIN C
    DIRECTION INPUT ;
    USE SIGNAL ;
    PORT
      LAYER M1 ;
        RECT 0.099 0.042 0.111 0.102 ;
    END
  END C
  PIN D
    DIRECTION INPUT ;
    USE SIGNAL ;
    PORT
      LAYER M1 ;
        RECT 0.141 0.042 0.153 0.102 ;
    END
  END D
  PIN VDD
    DIRECTION INOUT ;
    USE POWER ;
    SHAPE ABUTMENT ;
    PORT
      LAYER MBPR ;
        RECT -0.009 0.1075 0.219 0.1325 ;
    END
  END VDD
  PIN VSS
    DIRECTION INOUT ;
    USE GROUND ;
    SHAPE ABUTMENT ;
    PORT
      LAYER MBPR ;
        RECT -0.009 -0.0125 0.219 0.0125 ;
    END
  END VSS
  PIN Y
    DIRECTION OUTPUT ;
    USE SIGNAL ;
    PORT
      LAYER M1 ;
        RECT 0.183 0.018 0.195 0.102 ;
        RECT 0.057 0.018 0.195 0.03 ;
    END
  END Y
  OBS
    LAYER VBPR ;
      RECT 0.011 -0.006 0.031 0.006 ;
      RECT 0.011 0.114 0.031 0.126 ;
      RECT 0.095 -0.006 0.115 0.006 ;
      RECT 0.179 -0.006 0.199 0.006 ;
  END
END NOR4x1

MACRO OAI21x1
  CLASS CORE ;
  ORIGIN 0 0 ;
  FOREIGN OAI21x1 0 0 ;
  SIZE 0.168 BY 0.12 ;
  SYMMETRY X Y ;
  SITE coreSite ;
  PIN A
    DIRECTION INPUT ;
    USE SIGNAL ;
    PORT
      LAYER M1 ;
        RECT 0.015 0.042 0.027 0.102 ;
    END
  END A
  PIN B
    DIRECTION INPUT ;
    USE SIGNAL ;
    PORT
      LAYER M1 ;
        RECT 0.057 0.042 0.069 0.102 ;
    END
  END B
  PIN C
    DIRECTION INPUT ;
    USE SIGNAL ;
    PORT
      LAYER M1 ;
        RECT 0.099 0.042 0.111 0.078 ;
    END
  END C
  PIN VDD
    DIRECTION INOUT ;
    USE POWER ;
    SHAPE ABUTMENT ;
    PORT
      LAYER MBPR ;
        RECT -0.009 0.1075 0.177 0.1325 ;
    END
  END VDD
  PIN VSS
    DIRECTION INOUT ;
    USE GROUND ;
    SHAPE ABUTMENT ;
    PORT
      LAYER MBPR ;
        RECT -0.009 -0.0125 0.177 0.0125 ;
    END
  END VSS
  PIN Y
    DIRECTION OUTPUT ;
    USE SIGNAL ;
    PORT
      LAYER M1 ;
        RECT 0.099 0.09 0.153 0.102 ;
        RECT 0.141 0.018 0.153 0.102 ;
    END
  END Y
  OBS
    LAYER M1 ;
      RECT 0.015 0.018 0.111 0.03 ;
    LAYER VBPR ;
      RECT 0.053 -0.006 0.073 0.006 ;
      RECT 0.011 0.114 0.031 0.126 ;
      RECT 0.137 0.114 0.157 0.126 ;
  END
END OAI21x1

MACRO OAI221x1
  CLASS CORE ;
  ORIGIN 0 0 ;
  FOREIGN OAI221x1 0 0 ;
  SIZE 0.252 BY 0.12 ;
  SYMMETRY X Y ;
  SITE coreSite ;
  PIN A
    DIRECTION INPUT ;
    USE SIGNAL ;
    PORT
      LAYER M1 ;
        RECT 0.015 0.042 0.027 0.102 ;
    END
  END A
  PIN B
    DIRECTION INPUT ;
    USE SIGNAL ;
    PORT
      LAYER M1 ;
        RECT 0.057 0.042 0.069 0.102 ;
    END
  END B
  PIN C
    DIRECTION INPUT ;
    USE SIGNAL ;
    PORT
      LAYER M1 ;
        RECT 0.141 0.042 0.153 0.078 ;
    END
  END C
  PIN D
    DIRECTION INPUT ;
    USE SIGNAL ;
    PORT
      LAYER M1 ;
        RECT 0.225 0.042 0.237 0.078 ;
    END
  END D
  PIN E
    DIRECTION INPUT ;
    USE SIGNAL ;
    PORT
      LAYER M1 ;
        RECT 0.099 0.042 0.111 0.078 ;
    END
  END E
  PIN VDD
    DIRECTION INOUT ;
    USE POWER ;
    SHAPE ABUTMENT ;
    PORT
      LAYER MBPR ;
        RECT -0.009 0.1075 0.261 0.1325 ;
    END
  END VDD
  PIN VSS
    DIRECTION INOUT ;
    USE GROUND ;
    SHAPE ABUTMENT ;
    PORT
      LAYER MBPR ;
        RECT -0.009 -0.0125 0.261 0.0125 ;
    END
  END VSS
  PIN Y
    DIRECTION OUTPUT ;
    USE SIGNAL ;
    PORT
      LAYER M1 ;
        RECT 0.099 0.09 0.237 0.102 ;
        RECT 0.183 0.042 0.195 0.102 ;
    END
  END Y
  OBS
    LAYER M1 ;
      RECT 0.141 0.018 0.237 0.03 ;
      RECT 0.015 0.018 0.111 0.03 ;
    LAYER VBPR ;
      RECT 0.053 -0.006 0.073 0.006 ;
      RECT 0.011 0.114 0.031 0.126 ;
      RECT 0.137 0.114 0.157 0.126 ;
  END
END OAI221x1

MACRO OAI222x1
  CLASS CORE ;
  ORIGIN 0 0 ;
  FOREIGN OAI222x1 0 0 ;
  SIZE 0.336 BY 0.12 ;
  SYMMETRY X Y ;
  SITE coreSite ;
  PIN A
    DIRECTION INPUT ;
    USE SIGNAL ;
    PORT
      LAYER M1 ;
        RECT 0.015 0.018 0.027 0.102 ;
    END
  END A
  PIN B
    DIRECTION INPUT ;
    USE SIGNAL ;
    PORT
      LAYER M1 ;
        RECT 0.057 0.042 0.069 0.102 ;
    END
  END B
  PIN C
    DIRECTION INPUT ;
    USE SIGNAL ;
    PORT
      LAYER M1 ;
        RECT 0.099 0.066 0.174 0.078 ;
        RECT 0.099 0.066 0.111 0.102 ;
    END
  END C
  PIN D
    DIRECTION INPUT ;
    USE SIGNAL ;
    PORT
      LAYER M1 ;
        RECT 0.211 0.042 0.223 0.078 ;
    END
  END D
  PIN E
    DIRECTION INPUT ;
    USE SIGNAL ;
    PORT
      LAYER M1 ;
        RECT 0.239 0.042 0.251 0.078 ;
    END
  END E
  PIN F
    DIRECTION INPUT ;
    USE SIGNAL ;
    PORT
      LAYER M1 ;
        RECT 0.309 0.042 0.321 0.078 ;
    END
  END F
  PIN VDD
    DIRECTION INOUT ;
    USE POWER ;
    SHAPE ABUTMENT ;
    PORT
      LAYER MBPR ;
        RECT -0.009 0.1075 0.345 0.1325 ;
    END
  END VDD
  PIN VSS
    DIRECTION INOUT ;
    USE GROUND ;
    SHAPE ABUTMENT ;
    PORT
      LAYER MBPR ;
        RECT -0.009 -0.0125 0.345 0.0125 ;
    END
  END VSS
  PIN Y
    DIRECTION OUTPUT ;
    USE SIGNAL ;
    PORT
      LAYER M1 ;
        RECT 0.141 0.09 0.321 0.102 ;
        RECT 0.267 0.042 0.279 0.102 ;
    END
  END Y
  OBS
    LAYER M1 ;
      RECT 0.099 0.042 0.195 0.054 ;
      RECT 0.099 0.018 0.111 0.054 ;
      RECT 0.057 0.018 0.111 0.03 ;
      RECT 0.141 0.018 0.321 0.03 ;
    LAYER VBPR ;
      RECT 0.011 -0.006 0.031 0.006 ;
      RECT 0.011 0.114 0.031 0.126 ;
      RECT 0.095 -0.006 0.115 0.006 ;
      RECT 0.221 0.114 0.241 0.126 ;
  END
END OAI222x1

MACRO OAI22x1
  CLASS CORE ;
  ORIGIN 0 0 ;
  FOREIGN OAI22x1 0 0 ;
  SIZE 0.21 BY 0.12 ;
  SYMMETRY X Y ;
  SITE coreSite ;
  PIN A
    DIRECTION INPUT ;
    USE SIGNAL ;
    PORT
      LAYER M1 ;
        RECT 0.015 0.042 0.027 0.102 ;
    END
  END A
  PIN B
    DIRECTION INPUT ;
    USE SIGNAL ;
    PORT
      LAYER M1 ;
        RECT 0.057 0.042 0.069 0.102 ;
    END
  END B
  PIN C
    DIRECTION INPUT ;
    USE SIGNAL ;
    PORT
      LAYER M1 ;
        RECT 0.099 0.042 0.111 0.078 ;
    END
  END C
  PIN D
    DIRECTION INPUT ;
    USE SIGNAL ;
    PORT
      LAYER M1 ;
        RECT 0.183 0.042 0.195 0.102 ;
    END
  END D
  PIN VDD
    DIRECTION INOUT ;
    USE POWER ;
    SHAPE ABUTMENT ;
    PORT
      LAYER MBPR ;
        RECT -0.009 0.1075 0.219 0.1325 ;
    END
  END VDD
  PIN VSS
    DIRECTION INOUT ;
    USE GROUND ;
    SHAPE ABUTMENT ;
    PORT
      LAYER MBPR ;
        RECT -0.009 -0.0125 0.219 0.0125 ;
    END
  END VSS
  PIN Y
    DIRECTION OUTPUT ;
    USE SIGNAL ;
    PORT
      LAYER M1 ;
        RECT 0.099 0.09 0.153 0.102 ;
        RECT 0.141 0.042 0.153 0.102 ;
    END
  END Y
  OBS
    LAYER M1 ;
      RECT 0.015 0.018 0.195 0.03 ;
    LAYER VBPR ;
      RECT 0.053 -0.006 0.073 0.006 ;
      RECT 0.011 0.114 0.031 0.126 ;
      RECT 0.179 0.114 0.199 0.126 ;
  END
END OAI22x1

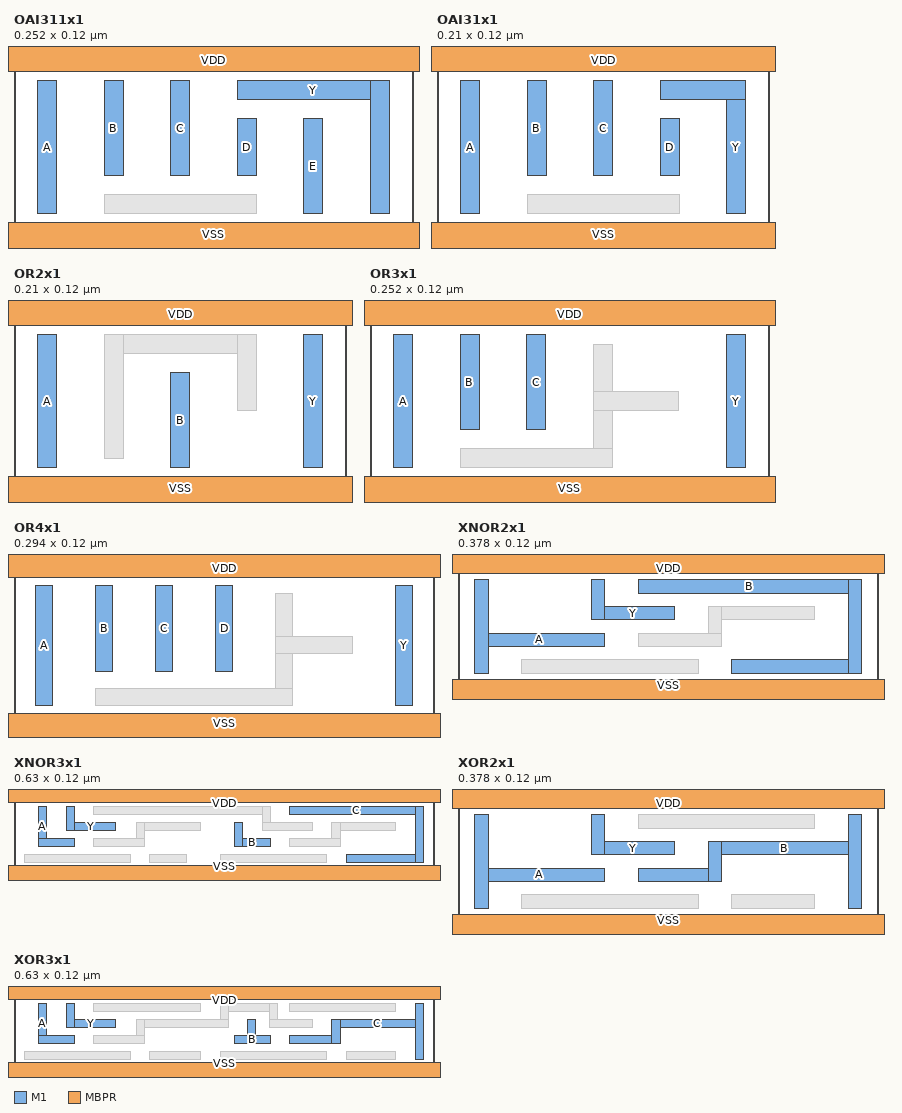
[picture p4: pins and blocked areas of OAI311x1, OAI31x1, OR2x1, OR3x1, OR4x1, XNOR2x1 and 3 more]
MACRO OAI311x1
  CLASS CORE ;
  ORIGIN 0 0 ;
  FOREIGN OAI311x1 0 0 ;
  SIZE 0.252 BY 0.12 ;
  SYMMETRY X Y ;
  SITE coreSite ;
  PIN A
    DIRECTION INPUT ;
    USE SIGNAL ;
    PORT
      LAYER M1 ;
        RECT 0.015 0.018 0.027 0.102 ;
    END
  END A
  PIN B
    DIRECTION INPUT ;
    USE SIGNAL ;
    PORT
      LAYER M1 ;
        RECT 0.057 0.042 0.069 0.102 ;
    END
  END B
  PIN C
    DIRECTION INPUT ;
    USE SIGNAL ;
    PORT
      LAYER M1 ;
        RECT 0.099 0.042 0.111 0.102 ;
    END
  END C
  PIN D
    DIRECTION INPUT ;
    USE SIGNAL ;
    PORT
      LAYER M1 ;
        RECT 0.141 0.042 0.153 0.078 ;
    END
  END D
  PIN E
    DIRECTION INPUT ;
    USE SIGNAL ;
    PORT
      LAYER M1 ;
        RECT 0.183 0.018 0.195 0.078 ;
    END
  END E
  PIN VDD
    DIRECTION INOUT ;
    USE POWER ;
    SHAPE ABUTMENT ;
    PORT
      LAYER MBPR ;
        RECT -0.009 0.1075 0.261 0.1325 ;
    END
  END VDD
  PIN VSS
    DIRECTION INOUT ;
    USE GROUND ;
    SHAPE ABUTMENT ;
    PORT
      LAYER MBPR ;
        RECT -0.009 -0.0125 0.261 0.0125 ;
    END
  END VSS
  PIN Y
    DIRECTION OUTPUT ;
    USE SIGNAL ;
    PORT
      LAYER M1 ;
        RECT 0.141 0.09 0.237 0.102 ;
        RECT 0.225 0.018 0.237 0.102 ;
    END
  END Y
  OBS
    LAYER M1 ;
      RECT 0.057 0.018 0.153 0.03 ;
    LAYER VBPR ;
      RECT 0.011 -0.006 0.031 0.006 ;
      RECT 0.011 0.114 0.031 0.126 ;
      RECT 0.095 -0.006 0.115 0.006 ;
      RECT 0.179 0.114 0.199 0.126 ;
  END
END OAI311x1

MACRO OAI31x1
  CLASS CORE ;
  ORIGIN 0 0 ;
  FOREIGN OAI31x1 0 0 ;
  SIZE 0.21 BY 0.12 ;
  SYMMETRY X Y ;
  SITE coreSite ;
  PIN A
    DIRECTION INPUT ;
    USE SIGNAL ;
    PORT
      LAYER M1 ;
        RECT 0.015 0.018 0.027 0.102 ;
    END
  END A
  PIN B
    DIRECTION INPUT ;
    USE SIGNAL ;
    PORT
      LAYER M1 ;
        RECT 0.057 0.042 0.069 0.102 ;
    END
  END B
  PIN C
    DIRECTION INPUT ;
    USE SIGNAL ;
    PORT
      LAYER M1 ;
        RECT 0.099 0.042 0.111 0.102 ;
    END
  END C
  PIN D
    DIRECTION INPUT ;
    USE SIGNAL ;
    PORT
      LAYER M1 ;
        RECT 0.141 0.042 0.153 0.078 ;
    END
  END D
  PIN VDD
    DIRECTION INOUT ;
    USE POWER ;
    SHAPE ABUTMENT ;
    PORT
      LAYER MBPR ;
        RECT -0.009 0.1075 0.219 0.1325 ;
    END
  END VDD
  PIN VSS
    DIRECTION INOUT ;
    USE GROUND ;
    SHAPE ABUTMENT ;
    PORT
      LAYER MBPR ;
        RECT -0.009 -0.0125 0.219 0.0125 ;
    END
  END VSS
  PIN Y
    DIRECTION OUTPUT ;
    USE SIGNAL ;
    PORT
      LAYER M1 ;
        RECT 0.141 0.09 0.195 0.102 ;
        RECT 0.183 0.018 0.195 0.102 ;
    END
  END Y
  OBS
    LAYER M1 ;
      RECT 0.057 0.018 0.153 0.03 ;
    LAYER VBPR ;
      RECT 0.011 -0.006 0.031 0.006 ;
      RECT 0.011 0.114 0.031 0.126 ;
      RECT 0.095 -0.006 0.115 0.006 ;
      RECT 0.179 0.114 0.199 0.126 ;
  END
END OAI31x1

MACRO OR2x1
  CLASS CORE ;
  ORIGIN 0 0 ;
  FOREIGN OR2x1 0 0 ;
  SIZE 0.21 BY 0.12 ;
  SYMMETRY X Y ;
  SITE coreSite ;
  PIN A
    DIRECTION INPUT ;
    USE SIGNAL ;
    PORT
      LAYER M1 ;
        RECT 0.015 0.018 0.027 0.102 ;
    END
  END A
  PIN B
    DIRECTION INPUT ;
    USE SIGNAL ;
    PORT
      LAYER M1 ;
        RECT 0.099 0.018 0.111 0.078 ;
    END
  END B
  PIN VDD
    DIRECTION INOUT ;
    USE POWER ;
    SHAPE ABUTMENT ;
    PORT
      LAYER MBPR ;
        RECT -0.009 0.1075 0.219 0.1325 ;
    END
  END VDD
  PIN VSS
    DIRECTION INOUT ;
    USE GROUND ;
    SHAPE ABUTMENT ;
    PORT
      LAYER MBPR ;
        RECT -0.009 -0.0125 0.219 0.0125 ;
    END
  END VSS
  PIN Y
    DIRECTION OUTPUT ;
    USE SIGNAL ;
    PORT
      LAYER M1 ;
        RECT 0.183 0.018 0.195 0.102 ;
    END
  END Y
  OBS
    LAYER M1 ;
      RECT 0.057 0.09 0.153 0.102 ;
      RECT 0.141 0.054 0.153 0.102 ;
      RECT 0.057 0.024 0.069 0.102 ;
    LAYER VBPR ;
      RECT 0.011 -0.006 0.031 0.006 ;
      RECT 0.011 0.114 0.031 0.126 ;
      RECT 0.095 -0.006 0.115 0.006 ;
      RECT 0.137 -0.006 0.157 0.006 ;
      RECT 0.137 0.114 0.157 0.126 ;
  END
END OR2x1

MACRO OR3x1
  CLASS CORE ;
  ORIGIN 0 0 ;
  FOREIGN OR3x1 0 0 ;
  SIZE 0.252 BY 0.12 ;
  SYMMETRY X Y ;
  SITE coreSite ;
  PIN A
    DIRECTION INPUT ;
    USE SIGNAL ;
    PORT
      LAYER M1 ;
        RECT 0.015 0.018 0.027 0.102 ;
    END
  END A
  PIN B
    DIRECTION INPUT ;
    USE SIGNAL ;
    PORT
      LAYER M1 ;
        RECT 0.057 0.042 0.069 0.102 ;
    END
  END B
  PIN C
    DIRECTION INPUT ;
    USE SIGNAL ;
    PORT
      LAYER M1 ;
        RECT 0.099 0.042 0.111 0.102 ;
    END
  END C
  PIN VDD
    DIRECTION INOUT ;
    USE POWER ;
    SHAPE ABUTMENT ;
    PORT
      LAYER MBPR ;
        RECT -0.009 0.1075 0.261 0.1325 ;
    END
  END VDD
  PIN VSS
    DIRECTION INOUT ;
    USE GROUND ;
    SHAPE ABUTMENT ;
    PORT
      LAYER MBPR ;
        RECT -0.009 -0.0125 0.261 0.0125 ;
    END
  END VSS
  PIN Y
    DIRECTION OUTPUT ;
    USE SIGNAL ;
    PORT
      LAYER M1 ;
        RECT 0.225 0.018 0.237 0.102 ;
    END
  END Y
  OBS
    LAYER M1 ;
      RECT 0.141 0.018 0.153 0.096 ;
      RECT 0.141 0.054 0.195 0.066 ;
      RECT 0.057 0.018 0.153 0.03 ;
    LAYER VBPR ;
      RECT 0.011 -0.006 0.031 0.006 ;
      RECT 0.011 0.114 0.031 0.126 ;
      RECT 0.095 -0.006 0.115 0.006 ;
      RECT 0.179 -0.006 0.199 0.006 ;
      RECT 0.179 0.114 0.199 0.126 ;
  END
END OR3x1

MACRO OR4x1
  CLASS CORE ;
  ORIGIN 0 0 ;
  FOREIGN OR4x1 0 0 ;
  SIZE 0.294 BY 0.12 ;
  SYMMETRY X Y ;
  SITE coreSite ;
  PIN A
    DIRECTION INPUT ;
    USE SIGNAL ;
    PORT
      LAYER M1 ;
        RECT 0.015 0.018 0.027 0.102 ;
    END
  END A
  PIN B
    DIRECTION INPUT ;
    USE SIGNAL ;
    PORT
      LAYER M1 ;
        RECT 0.057 0.042 0.069 0.102 ;
    END
  END B
  PIN C
    DIRECTION INPUT ;
    USE SIGNAL ;
    PORT
      LAYER M1 ;
        RECT 0.099 0.042 0.111 0.102 ;
    END
  END C
  PIN D
    DIRECTION INPUT ;
    USE SIGNAL ;
    PORT
      LAYER M1 ;
        RECT 0.141 0.042 0.153 0.102 ;
    END
  END D
  PIN VDD
    DIRECTION INOUT ;
    USE POWER ;
    SHAPE ABUTMENT ;
    PORT
      LAYER MBPR ;
        RECT -0.009 0.1075 0.303 0.1325 ;
    END
  END VDD
  PIN VSS
    DIRECTION INOUT ;
    USE GROUND ;
    SHAPE ABUTMENT ;
    PORT
      LAYER MBPR ;
        RECT -0.009 -0.0125 0.303 0.0125 ;
    END
  END VSS
  PIN Y
    DIRECTION OUTPUT ;
    USE SIGNAL ;
    PORT
      LAYER M1 ;
        RECT 0.267 0.018 0.279 0.102 ;
    END
  END Y
  OBS
    LAYER M1 ;
      RECT 0.183 0.018 0.195 0.096 ;
      RECT 0.183 0.054 0.237 0.066 ;
      RECT 0.057 0.018 0.195 0.03 ;
    LAYER VBPR ;
      RECT 0.011 -0.006 0.031 0.006 ;
      RECT 0.011 0.114 0.031 0.126 ;
      RECT 0.095 -0.006 0.115 0.006 ;
      RECT 0.179 -0.006 0.199 0.006 ;
      RECT 0.221 -0.006 0.241 0.006 ;
      RECT 0.221 0.114 0.241 0.126 ;
  END
END OR4x1

MACRO XNOR2x1
  CLASS CORE ;
  ORIGIN 0 0 ;
  FOREIGN XNOR2x1 0 0 ;
  SIZE 0.378 BY 0.12 ;
  SYMMETRY X Y ;
  SITE coreSite ;
  PIN A
    DIRECTION INPUT ;
    USE SIGNAL ;
    PORT
      LAYER M1 ;
        RECT 0.015 0.042 0.132 0.054 ;
        RECT 0.015 0.018 0.027 0.102 ;
    END
  END A
  PIN B
    DIRECTION INPUT ;
    USE SIGNAL ;
    PORT
      LAYER M1 ;
        RECT 0.162 0.09 0.363 0.102 ;
        RECT 0.351 0.018 0.363 0.102 ;
        RECT 0.246 0.018 0.363 0.03 ;
    END
  END B
  PIN VDD
    DIRECTION INOUT ;
    USE POWER ;
    SHAPE ABUTMENT ;
    PORT
      LAYER MBPR ;
        RECT -0.009 0.1075 0.387 0.1325 ;
    END
  END VDD
  PIN VSS
    DIRECTION INOUT ;
    USE GROUND ;
    SHAPE ABUTMENT ;
    PORT
      LAYER MBPR ;
        RECT -0.009 -0.0125 0.387 0.0125 ;
    END
  END VSS
  PIN Y
    DIRECTION OUTPUT ;
    USE SIGNAL ;
    PORT
      LAYER M1 ;
        RECT 0.12 0.066 0.195 0.078 ;
        RECT 0.12 0.066 0.132 0.102 ;
    END
  END Y
  OBS
    LAYER M1 ;
      RECT 0.225 0.066 0.321 0.078 ;
      RECT 0.225 0.042 0.237 0.078 ;
      RECT 0.162 0.042 0.237 0.054 ;
      RECT 0.057 0.018 0.216 0.03 ;
    LAYER VBPR ;
      RECT 0.011 -0.006 0.031 0.006 ;
      RECT 0.011 0.114 0.031 0.126 ;
      RECT 0.095 -0.006 0.115 0.006 ;
      RECT 0.095 0.114 0.115 0.126 ;
      RECT 0.263 -0.006 0.283 0.006 ;
      RECT 0.263 0.114 0.283 0.126 ;
      RECT 0.347 -0.006 0.367 0.006 ;
      RECT 0.347 0.114 0.367 0.126 ;
  END
  PROPERTY pathCL "yes" ;
  PROPERTY arrayDisplay "Full" ;
  PROPERTY instLabel "master" ;
  PROPERTY startLevel 0 ;
  PROPERTY stopLevel 0 ;
  PROPERTY scrollPercent 25 ;
  PROPERTY gridSpacing 1 ;
  PROPERTY gridMultiple 5 ;
  PROPERTY xSnapSpacing 0.001 ;
  PROPERTY ySnapSpacing 0.001 ;
  PROPERTY snapMode "orthogonal" ;
  PROPERTY segSnapMode "orthogonal" ;
  PROPERTY instanceDrawingMode "BBox" ;
  PROPERTY lppVisibilityMode "donotCheckValidity" ;
  PROPERTY filterSize 6 ;
  PROPERTY filterSizeDrawingStyle "empty" ;
  PROPERTY displayResolution "Medium" ;
  PROPERTY dimmingScope "none" ;
  PROPERTY dimmingIntensity 50 ;
  PROPERTY autoZoomMode "Pan" ;
  PROPERTY autoZoomScale 90 ;
  PROPERTY mergeScope "pcells" ;
END XNOR2x1

MACRO XNOR3x1
  CLASS CORE ;
  ORIGIN 0 0 ;
  FOREIGN XNOR3x1 0 0 ;
  SIZE 0.63 BY 0.12 ;
  SYMMETRY X Y ;
  SITE coreSite ;
  PIN A
    DIRECTION INPUT ;
    USE SIGNAL ;
    PORT
      LAYER M1 ;
        RECT 0.036 0.042 0.09 0.054 ;
        RECT 0.036 0.042 0.048 0.102 ;
    END
  END A
  PIN B
    DIRECTION INPUT ;
    USE SIGNAL ;
    PORT
      LAYER M1 ;
        RECT 0.33 0.042 0.384 0.054 ;
        RECT 0.33 0.042 0.342 0.078 ;
    END
  END B
  PIN C
    DIRECTION INPUT ;
    USE SIGNAL ;
    PORT
      LAYER M1 ;
        RECT 0.414 0.09 0.615 0.102 ;
        RECT 0.603 0.018 0.615 0.102 ;
        RECT 0.498 0.018 0.615 0.03 ;
    END
  END C
  PIN VDD
    DIRECTION INOUT ;
    USE POWER ;
    SHAPE ABUTMENT ;
    PORT
      LAYER MBPR ;
        RECT -0.009 0.1075 0.639 0.1325 ;
    END
  END VDD
  PIN VSS
    DIRECTION INOUT ;
    USE GROUND ;
    SHAPE ABUTMENT ;
    PORT
      LAYER MBPR ;
        RECT -0.009 -0.0125 0.639 0.0125 ;
    END
  END VSS
  PIN Y
    DIRECTION OUTPUT ;
    USE SIGNAL ;
    PORT
      LAYER M1 ;
        RECT 0.078 0.066 0.153 0.078 ;
        RECT 0.078 0.066 0.09 0.102 ;
    END
  END Y
  OBS
    LAYER M1 ;
      RECT 0.477 0.066 0.572 0.078 ;
      RECT 0.477 0.042 0.489 0.078 ;
      RECT 0.414 0.042 0.489 0.054 ;
      RECT 0.12 0.09 0.384 0.102 ;
      RECT 0.372 0.066 0.384 0.102 ;
      RECT 0.372 0.066 0.447 0.078 ;
      RECT 0.183 0.066 0.279 0.078 ;
      RECT 0.183 0.042 0.195 0.078 ;
      RECT 0.12 0.042 0.195 0.054 ;
      RECT 0.309 0.018 0.468 0.03 ;
      RECT 0.204 0.018 0.258 0.03 ;
      RECT 0.015 0.018 0.174 0.03 ;
    LAYER VBPR ;
      RECT 0.053 -0.006 0.073 0.006 ;
      RECT 0.053 0.114 0.073 0.126 ;
      RECT 0.221 -0.006 0.241 0.006 ;
      RECT 0.221 0.114 0.241 0.126 ;
      RECT 0.347 -0.006 0.367 0.006 ;
      RECT 0.347 0.114 0.367 0.126 ;
      RECT 0.515 -0.006 0.535 0.006 ;
      RECT 0.515 0.114 0.535 0.126 ;
      RECT 0.557 -0.006 0.577 0.006 ;
      RECT 0.557 0.114 0.577 0.126 ;
      RECT 0.599 -0.006 0.619 0.006 ;
      RECT 0.599 0.114 0.619 0.126 ;
  END
END XNOR3x1

MACRO XOR2x1
  CLASS CORE ;
  ORIGIN 0 0 ;
  FOREIGN XOR2x1 0 0 ;
  SIZE 0.378 BY 0.12 ;
  SYMMETRY X Y ;
  SITE coreSite ;
  PIN A
    DIRECTION INPUT ;
    USE SIGNAL ;
    PORT
      LAYER M1 ;
        RECT 0.015 0.042 0.132 0.054 ;
        RECT 0.015 0.018 0.027 0.102 ;
    END
  END A
  PIN B
    DIRECTION INPUT ;
    USE SIGNAL ;
    PORT
      LAYER M1 ;
        RECT 0.351 0.018 0.363 0.102 ;
        RECT 0.225 0.066 0.363 0.078 ;
        RECT 0.225 0.042 0.237 0.078 ;
        RECT 0.162 0.042 0.237 0.054 ;
    END
  END B
  PIN VDD
    DIRECTION INOUT ;
    USE POWER ;
    SHAPE ABUTMENT ;
    PORT
      LAYER MBPR ;
        RECT -0.009 0.1075 0.387 0.1325 ;
    END
  END VDD
  PIN VSS
    DIRECTION INOUT ;
    USE GROUND ;
    SHAPE ABUTMENT ;
    PORT
      LAYER MBPR ;
        RECT -0.009 -0.0125 0.387 0.0125 ;
    END
  END VSS
  PIN Y
    DIRECTION OUTPUT ;
    USE SIGNAL ;
    PORT
      LAYER M1 ;
        RECT 0.12 0.066 0.195 0.078 ;
        RECT 0.12 0.066 0.132 0.102 ;
    END
  END Y
  OBS
    LAYER M1 ;
      RECT 0.246 0.018 0.321 0.03 ;
      RECT 0.162 0.09 0.321 0.102 ;
      RECT 0.057 0.018 0.216 0.03 ;
    LAYER VBPR ;
      RECT 0.011 -0.006 0.031 0.006 ;
      RECT 0.011 0.114 0.031 0.126 ;
      RECT 0.095 -0.006 0.115 0.006 ;
      RECT 0.095 0.114 0.115 0.126 ;
      RECT 0.263 -0.006 0.283 0.006 ;
      RECT 0.263 0.114 0.283 0.126 ;
      RECT 0.347 -0.006 0.367 0.006 ;
      RECT 0.347 0.114 0.367 0.126 ;
  END
  PROPERTY pathCL "yes" ;
  PROPERTY arrayDisplay "Full" ;
  PROPERTY instLabel "master" ;
  PROPERTY startLevel 0 ;
  PROPERTY stopLevel 0 ;
  PROPERTY scrollPercent 25 ;
  PROPERTY gridSpacing 1 ;
  PROPERTY gridMultiple 5 ;
  PROPERTY xSnapSpacing 0.001 ;
  PROPERTY ySnapSpacing 0.001 ;
  PROPERTY snapMode "orthogonal" ;
  PROPERTY segSnapMode "orthogonal" ;
  PROPERTY instanceDrawingMode "BBox" ;
  PROPERTY lppVisibilityMode "donotCheckValidity" ;
  PROPERTY filterSize 6 ;
  PROPERTY filterSizeDrawingStyle "empty" ;
  PROPERTY displayResolution "Medium" ;
  PROPERTY dimmingScope "none" ;
  PROPERTY dimmingIntensity 50 ;
  PROPERTY autoZoomMode "Pan" ;
  PROPERTY autoZoomScale 90 ;
  PROPERTY mergeScope "pcells" ;
END XOR2x1

MACRO XOR3x1
  CLASS CORE ;
  ORIGIN 0 0 ;
  FOREIGN XOR3x1 0 0 ;
  SIZE 0.63 BY 0.12 ;
  SYMMETRY X Y ;
  SITE coreSite ;
  PIN A
    DIRECTION INPUT ;
    USE SIGNAL ;
    PORT
      LAYER M1 ;
        RECT 0.036 0.042 0.09 0.054 ;
        RECT 0.036 0.042 0.048 0.102 ;
    END
  END A
  PIN B
    DIRECTION INPUT ;
    USE SIGNAL ;
    PORT
      LAYER M1 ;
        RECT 0.33 0.042 0.384 0.054 ;
        RECT 0.351 0.042 0.363 0.078 ;
    END
  END B
  PIN C
    DIRECTION INPUT ;
    USE SIGNAL ;
    PORT
      LAYER M1 ;
        RECT 0.603 0.018 0.615 0.102 ;
        RECT 0.477 0.066 0.615 0.078 ;
        RECT 0.477 0.042 0.489 0.078 ;
        RECT 0.414 0.042 0.489 0.054 ;
    END
  END C
  PIN VDD
    DIRECTION INOUT ;
    USE POWER ;
    SHAPE ABUTMENT ;
    PORT
      LAYER MBPR ;
        RECT -0.009 0.1075 0.639 0.1325 ;
    END
  END VDD
  PIN VSS
    DIRECTION INOUT ;
    USE GROUND ;
    SHAPE ABUTMENT ;
    PORT
      LAYER MBPR ;
        RECT -0.009 -0.0125 0.639 0.0125 ;
    END
  END VSS
  PIN Y
    DIRECTION OUTPUT ;
    USE SIGNAL ;
    PORT
      LAYER M1 ;
        RECT 0.078 0.066 0.153 0.078 ;
        RECT 0.078 0.066 0.09 0.102 ;
    END
  END Y
  OBS
    LAYER M1 ;
      RECT 0.309 0.09 0.395 0.102 ;
      RECT 0.383 0.066 0.395 0.102 ;
      RECT 0.309 0.066 0.321 0.102 ;
      RECT 0.383 0.066 0.447 0.078 ;
      RECT 0.183 0.066 0.321 0.078 ;
      RECT 0.183 0.042 0.195 0.078 ;
      RECT 0.12 0.042 0.195 0.054 ;
      RECT 0.498 0.018 0.573 0.03 ;
      RECT 0.414 0.09 0.573 0.102 ;
      RECT 0.309 0.018 0.468 0.03 ;
      RECT 0.204 0.018 0.279 0.03 ;
      RECT 0.12 0.09 0.279 0.102 ;
      RECT 0.015 0.018 0.174 0.03 ;
    LAYER VBPR ;
      RECT 0.053 -0.006 0.073 0.006 ;
      RECT 0.053 0.114 0.073 0.126 ;
      RECT 0.221 -0.006 0.241 0.006 ;
      RECT 0.221 0.114 0.241 0.126 ;
      RECT 0.347 -0.006 0.367 0.006 ;
      RECT 0.347 0.114 0.367 0.126 ;
      RECT 0.515 -0.006 0.535 0.006 ;
      RECT 0.515 0.114 0.535 0.126 ;
      RECT 0.599 -0.006 0.619 0.006 ;
      RECT 0.599 0.114 0.619 0.126 ;
  END
  PROPERTY pathCL "yes" ;
  PROPERTY arrayDisplay "Full" ;
  PROPERTY instLabel "master" ;
  PROPERTY startLevel 0 ;
  PROPERTY stopLevel 0 ;
  PROPERTY scrollPercent 25 ;
  PROPERTY gridSpacing 1 ;
  PROPERTY gridMultiple 5 ;
  PROPERTY xSnapSpacing 0.001 ;
  PROPERTY ySnapSpacing 0.001 ;
  PROPERTY snapMode "orthogonal" ;
  PROPERTY segSnapMode "orthogonal" ;
  PROPERTY instanceDrawingMode "BBox" ;
  PROPERTY lppVisibilityMode "donotCheckValidity" ;
  PROPERTY filterSize 6 ;
  PROPERTY filterSizeDrawingStyle "empty" ;
  PROPERTY displayResolution "Medium" ;
  PROPERTY dimmingScope "none" ;
  PROPERTY dimmingIntensity 50 ;
  PROPERTY autoZoomMode "Pan" ;
  PROPERTY autoZoomScale 90 ;
  PROPERTY mergeScope "pcells" ;
END XOR3x1

END LIBRARY
